VERSION 5.7 ;
  NOWIREEXTENSIONATPIN ON ;
  DIVIDERCHAR "/" ;
  BUSBITCHARS "[]" ;
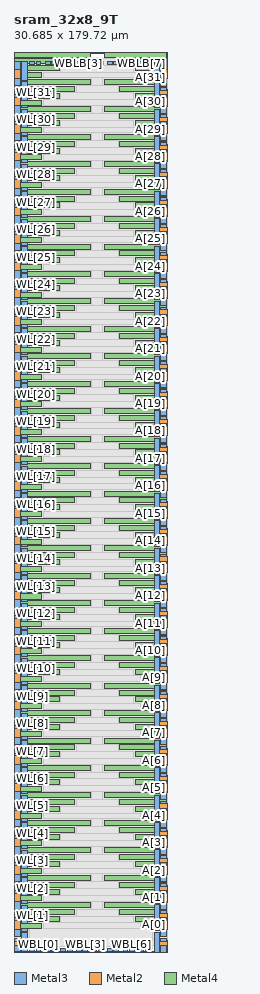
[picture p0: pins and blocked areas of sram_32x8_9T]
MACRO sram_32x8_9T
  CLASS BLOCK ;
  FOREIGN sram_32x8_9T ;
  ORIGIN 2.880 1.270 ;
  SIZE 30.685 BY 179.720 ;
  PIN VSS
    USE GROUND ;
    PORT
      LAYER Metal3 ;
        RECT -2.875 -1.250 -1.645 1.500 ;
    END
    PORT
      LAYER Metal3 ;
        RECT -2.875 1.785 -1.645 6.980 ;
    END
    PORT
      LAYER Metal3 ;
        RECT -2.875 7.265 -1.645 12.460 ;
    END
    PORT
      LAYER Metal3 ;
        RECT -2.875 12.745 -1.645 17.940 ;
    END
    PORT
      LAYER Metal3 ;
        RECT -2.875 18.225 -1.645 23.420 ;
    END
    PORT
      LAYER Metal3 ;
        RECT -2.875 23.705 -1.645 28.900 ;
    END
    PORT
      LAYER Metal3 ;
        RECT -2.875 29.185 -1.645 34.380 ;
    END
    PORT
      LAYER Metal3 ;
        RECT -2.875 34.665 -1.645 39.860 ;
    END
    PORT
      LAYER Metal3 ;
        RECT -2.875 40.145 -1.645 45.340 ;
    END
    PORT
      LAYER Metal3 ;
        RECT -2.875 45.625 -1.645 50.820 ;
    END
    PORT
      LAYER Metal3 ;
        RECT -2.875 51.105 -1.645 56.300 ;
    END
    PORT
      LAYER Metal3 ;
        RECT -2.875 56.585 -1.645 61.780 ;
    END
    PORT
      LAYER Metal3 ;
        RECT -2.875 62.065 -1.645 67.260 ;
    END
    PORT
      LAYER Metal3 ;
        RECT -2.875 67.545 -1.645 72.740 ;
    END
    PORT
      LAYER Metal3 ;
        RECT -2.875 73.025 -1.645 78.220 ;
    END
    PORT
      LAYER Metal3 ;
        RECT -2.875 78.505 -1.645 83.700 ;
    END
    PORT
      LAYER Metal3 ;
        RECT -2.875 83.985 -1.645 89.180 ;
    END
    PORT
      LAYER Metal3 ;
        RECT -2.875 89.465 -1.645 94.660 ;
    END
    PORT
      LAYER Metal3 ;
        RECT -2.875 94.945 -1.645 100.140 ;
    END
    PORT
      LAYER Metal3 ;
        RECT -2.875 100.425 -1.645 105.620 ;
    END
    PORT
      LAYER Metal3 ;
        RECT -2.875 105.905 -1.645 111.100 ;
    END
    PORT
      LAYER Metal3 ;
        RECT -2.875 111.385 -1.645 116.580 ;
    END
    PORT
      LAYER Metal3 ;
        RECT -2.875 116.865 -1.645 122.060 ;
    END
    PORT
      LAYER Metal3 ;
        RECT -2.875 122.345 -1.645 127.540 ;
    END
    PORT
      LAYER Metal3 ;
        RECT -2.875 127.825 -1.645 133.020 ;
    END
    PORT
      LAYER Metal3 ;
        RECT -2.875 133.305 -1.645 138.500 ;
    END
    PORT
      LAYER Metal3 ;
        RECT -2.875 138.785 -1.645 143.980 ;
    END
    PORT
      LAYER Metal3 ;
        RECT -2.875 144.265 -1.645 149.460 ;
    END
    PORT
      LAYER Metal3 ;
        RECT -2.875 149.745 -1.645 154.940 ;
    END
    PORT
      LAYER Metal3 ;
        RECT -2.875 155.225 -1.645 160.420 ;
    END
    PORT
      LAYER Metal3 ;
        RECT -2.875 160.705 -1.645 165.900 ;
    END
    PORT
      LAYER Metal3 ;
        RECT -2.875 166.185 -1.645 171.380 ;
    END
    PORT
      LAYER Metal3 ;
        RECT -2.875 171.665 -1.645 176.540 ;
    END
    PORT
      LAYER Metal3 ;
        RECT 26.440 171.640 27.580 176.545 ;
    END
    PORT
      LAYER Metal3 ;
        RECT 26.435 166.160 27.580 171.360 ;
    END
    PORT
      LAYER Metal3 ;
        RECT 26.435 160.680 27.580 165.880 ;
    END
    PORT
      LAYER Metal3 ;
        RECT 26.435 155.200 27.580 160.400 ;
    END
    PORT
      LAYER Metal3 ;
        RECT 26.435 149.720 27.580 154.920 ;
    END
    PORT
      LAYER Metal3 ;
        RECT 26.435 144.240 27.580 149.440 ;
    END
    PORT
      LAYER Metal3 ;
        RECT 26.435 138.760 27.580 143.960 ;
    END
    PORT
      LAYER Metal3 ;
        RECT 26.435 133.280 27.580 138.480 ;
    END
    PORT
      LAYER Metal3 ;
        RECT 26.435 127.800 27.580 133.000 ;
    END
    PORT
      LAYER Metal3 ;
        RECT 26.435 122.320 27.580 127.520 ;
    END
    PORT
      LAYER Metal3 ;
        RECT 26.435 116.840 27.580 122.040 ;
    END
    PORT
      LAYER Metal3 ;
        RECT 26.435 111.360 27.580 116.560 ;
    END
    PORT
      LAYER Metal3 ;
        RECT 26.435 105.880 27.580 111.080 ;
    END
    PORT
      LAYER Metal3 ;
        RECT 26.435 100.400 27.580 105.600 ;
    END
    PORT
      LAYER Metal3 ;
        RECT 26.435 94.920 27.580 100.120 ;
    END
    PORT
      LAYER Metal3 ;
        RECT 26.435 89.440 27.580 94.640 ;
    END
    PORT
      LAYER Metal3 ;
        RECT 26.435 83.960 27.580 89.160 ;
    END
    PORT
      LAYER Metal3 ;
        RECT 26.435 78.480 27.580 83.680 ;
    END
    PORT
      LAYER Metal3 ;
        RECT 26.435 73.000 27.580 78.200 ;
    END
    PORT
      LAYER Metal3 ;
        RECT 26.435 67.520 27.580 72.720 ;
    END
    PORT
      LAYER Metal3 ;
        RECT 26.435 62.040 27.580 67.240 ;
    END
    PORT
      LAYER Metal3 ;
        RECT 26.435 56.560 27.580 61.760 ;
    END
    PORT
      LAYER Metal3 ;
        RECT 26.435 51.080 27.580 56.280 ;
    END
    PORT
      LAYER Metal3 ;
        RECT 26.435 45.600 27.580 50.800 ;
    END
    PORT
      LAYER Metal3 ;
        RECT 26.435 40.120 27.580 45.320 ;
    END
    PORT
      LAYER Metal3 ;
        RECT 26.435 34.640 27.580 39.840 ;
    END
    PORT
      LAYER Metal3 ;
        RECT 26.435 29.160 27.580 34.360 ;
    END
    PORT
      LAYER Metal3 ;
        RECT 26.435 23.680 27.580 28.880 ;
    END
    PORT
      LAYER Metal3 ;
        RECT 26.435 18.200 27.580 23.400 ;
    END
    PORT
      LAYER Metal3 ;
        RECT 26.435 12.720 27.580 17.920 ;
    END
    PORT
      LAYER Metal3 ;
        RECT 26.435 7.240 27.580 12.440 ;
    END
    PORT
      LAYER Metal3 ;
        RECT 26.435 -1.270 27.580 1.480 ;
    END
    PORT
      LAYER Metal3 ;
        RECT 26.435 1.760 27.580 6.960 ;
    END
  END VSS
  PIN VDD
    USE POWER ;
    PORT
      LAYER Metal3 ;
        RECT -1.300 161.810 -0.130 167.010 ;
    END
    PORT
      LAYER Metal3 ;
        RECT -1.300 156.330 -0.130 161.530 ;
    END
    PORT
      LAYER Metal3 ;
        RECT -1.300 150.850 -0.130 156.050 ;
    END
    PORT
      LAYER Metal3 ;
        RECT -1.300 145.370 -0.130 150.570 ;
    END
    PORT
      LAYER Metal3 ;
        RECT -1.300 139.890 -0.130 145.090 ;
    END
    PORT
      LAYER Metal3 ;
        RECT -1.300 134.410 -0.130 139.610 ;
    END
    PORT
      LAYER Metal3 ;
        RECT -1.300 128.930 -0.130 134.130 ;
    END
    PORT
      LAYER Metal3 ;
        RECT -1.300 123.450 -0.130 128.650 ;
    END
    PORT
      LAYER Metal3 ;
        RECT -1.300 117.970 -0.130 123.170 ;
    END
    PORT
      LAYER Metal3 ;
        RECT -1.300 112.490 -0.130 117.690 ;
    END
    PORT
      LAYER Metal3 ;
        RECT -1.300 107.010 -0.130 112.210 ;
    END
    PORT
      LAYER Metal3 ;
        RECT -1.300 101.530 -0.130 106.730 ;
    END
    PORT
      LAYER Metal3 ;
        RECT -1.300 96.050 -0.130 101.250 ;
    END
    PORT
      LAYER Metal3 ;
        RECT -1.300 90.570 -0.130 95.770 ;
    END
    PORT
      LAYER Metal3 ;
        RECT -1.300 85.090 -0.130 90.290 ;
    END
    PORT
      LAYER Metal3 ;
        RECT -1.300 79.610 -0.130 84.810 ;
    END
    PORT
      LAYER Metal3 ;
        RECT -1.300 74.130 -0.130 79.330 ;
    END
    PORT
      LAYER Metal3 ;
        RECT -1.300 68.650 -0.130 73.850 ;
    END
    PORT
      LAYER Metal3 ;
        RECT -1.300 63.170 -0.130 68.370 ;
    END
    PORT
      LAYER Metal3 ;
        RECT -1.300 57.690 -0.130 62.890 ;
    END
    PORT
      LAYER Metal3 ;
        RECT -1.300 52.210 -0.130 57.410 ;
    END
    PORT
      LAYER Metal3 ;
        RECT -1.300 46.730 -0.130 51.930 ;
    END
    PORT
      LAYER Metal3 ;
        RECT -1.300 41.250 -0.130 46.450 ;
    END
    PORT
      LAYER Metal3 ;
        RECT -1.300 35.770 -0.130 40.970 ;
    END
    PORT
      LAYER Metal3 ;
        RECT -1.300 30.290 -0.130 35.490 ;
    END
    PORT
      LAYER Metal3 ;
        RECT -1.300 24.810 -0.130 30.010 ;
    END
    PORT
      LAYER Metal3 ;
        RECT -1.300 19.330 -0.130 24.530 ;
    END
    PORT
      LAYER Metal3 ;
        RECT -1.300 13.850 -0.130 19.050 ;
    END
    PORT
      LAYER Metal3 ;
        RECT -1.300 8.370 -0.130 13.570 ;
    END
    PORT
      LAYER Metal3 ;
        RECT -1.300 2.890 -0.130 8.090 ;
    END
    PORT
      LAYER Metal3 ;
        RECT -1.300 -1.240 -0.130 2.610 ;
    END
    PORT
      LAYER Metal3 ;
        RECT -1.300 167.290 -0.130 172.490 ;
    END
    PORT
      LAYER Metal3 ;
        RECT -1.300 172.770 -0.130 176.540 ;
    END
    PORT
      LAYER Metal3 ;
        RECT 25.135 -1.270 26.095 2.660 ;
    END
    PORT
      LAYER Metal3 ;
        RECT 25.135 2.940 26.095 8.140 ;
    END
    PORT
      LAYER Metal3 ;
        RECT 25.135 8.420 26.095 13.620 ;
    END
    PORT
      LAYER Metal3 ;
        RECT 25.135 13.900 26.095 19.100 ;
    END
    PORT
      LAYER Metal3 ;
        RECT 25.135 19.380 26.095 24.580 ;
    END
    PORT
      LAYER Metal3 ;
        RECT 25.135 24.860 26.095 30.060 ;
    END
    PORT
      LAYER Metal3 ;
        RECT 25.135 30.340 26.095 35.540 ;
    END
    PORT
      LAYER Metal3 ;
        RECT 25.135 35.820 26.095 41.020 ;
    END
    PORT
      LAYER Metal3 ;
        RECT 25.135 41.300 26.095 46.500 ;
    END
    PORT
      LAYER Metal3 ;
        RECT 25.135 46.780 26.095 51.980 ;
    END
    PORT
      LAYER Metal3 ;
        RECT 25.135 52.260 26.095 57.460 ;
    END
    PORT
      LAYER Metal3 ;
        RECT 25.135 57.740 26.095 62.940 ;
    END
    PORT
      LAYER Metal3 ;
        RECT 25.135 63.220 26.095 68.420 ;
    END
    PORT
      LAYER Metal3 ;
        RECT 25.135 68.700 26.095 73.900 ;
    END
    PORT
      LAYER Metal3 ;
        RECT 25.135 74.180 26.095 79.380 ;
    END
    PORT
      LAYER Metal3 ;
        RECT 25.135 79.660 26.095 84.860 ;
    END
    PORT
      LAYER Metal3 ;
        RECT 25.135 85.140 26.095 90.340 ;
    END
    PORT
      LAYER Metal3 ;
        RECT 25.135 90.620 26.095 95.820 ;
    END
    PORT
      LAYER Metal3 ;
        RECT 25.135 96.100 26.095 101.300 ;
    END
    PORT
      LAYER Metal3 ;
        RECT 25.135 101.580 26.095 106.780 ;
    END
    PORT
      LAYER Metal3 ;
        RECT 25.135 107.060 26.095 112.260 ;
    END
    PORT
      LAYER Metal3 ;
        RECT 25.135 112.540 26.095 117.740 ;
    END
    PORT
      LAYER Metal3 ;
        RECT 25.135 118.020 26.095 123.220 ;
    END
    PORT
      LAYER Metal3 ;
        RECT 25.135 123.500 26.095 128.700 ;
    END
    PORT
      LAYER Metal3 ;
        RECT 25.135 128.980 26.095 134.180 ;
    END
    PORT
      LAYER Metal3 ;
        RECT 25.135 134.460 26.095 139.660 ;
    END
    PORT
      LAYER Metal3 ;
        RECT 25.135 139.940 26.095 145.140 ;
    END
    PORT
      LAYER Metal3 ;
        RECT 25.135 145.420 26.095 150.620 ;
    END
    PORT
      LAYER Metal3 ;
        RECT 25.135 150.900 26.095 156.100 ;
    END
    PORT
      LAYER Metal3 ;
        RECT 25.135 156.380 26.095 161.580 ;
    END
    PORT
      LAYER Metal3 ;
        RECT 25.135 161.860 26.095 167.060 ;
    END
    PORT
      LAYER Metal3 ;
        RECT 25.135 167.340 26.095 172.540 ;
    END
    PORT
      LAYER Metal3 ;
        RECT 25.135 172.820 26.095 176.540 ;
    END
  END VDD
  PIN WBLB[0]
    ANTENNADIFFAREA 7.558400 ;
    PORT
      LAYER Metal3 ;
        RECT 0.260 -1.195 1.220 -0.500 ;
    END
    PORT
      LAYER Metal3 ;
        RECT 0.275 175.855 1.235 176.550 ;
    END
  END WBLB[0]
  PIN WBLB[1]
    ANTENNADIFFAREA 7.558400 ;
    PORT
      LAYER Metal3 ;
        RECT 3.370 -1.195 4.330 -0.500 ;
    END
    PORT
      LAYER Metal3 ;
        RECT 3.385 175.855 4.345 176.550 ;
    END
  END WBLB[1]
  PIN WBLB[2]
    ANTENNADIFFAREA 7.558400 ;
    PORT
      LAYER Metal3 ;
        RECT 6.480 -1.195 7.440 -0.500 ;
    END
    PORT
      LAYER Metal3 ;
        RECT 6.495 175.855 7.455 176.550 ;
    END
  END WBLB[2]
  PIN WBLB[3]
    ANTENNADIFFAREA 7.558400 ;
    PORT
      LAYER Metal3 ;
        RECT 9.590 -1.195 10.550 -0.500 ;
    END
    PORT
      LAYER Metal3 ;
        RECT 9.605 175.855 10.565 176.550 ;
    END
  END WBLB[3]
  PIN WBLB[4]
    ANTENNADIFFAREA 7.558400 ;
    PORT
      LAYER Metal3 ;
        RECT 12.700 -1.195 13.660 -0.500 ;
    END
    PORT
      LAYER Metal3 ;
        RECT 12.715 175.855 13.675 176.550 ;
    END
  END WBLB[4]
  PIN WBLB[5]
    ANTENNADIFFAREA 7.558400 ;
    PORT
      LAYER Metal3 ;
        RECT 15.810 -1.195 16.770 -0.500 ;
    END
    PORT
      LAYER Metal3 ;
        RECT 15.825 175.855 16.785 176.550 ;
    END
  END WBLB[5]
  PIN WBLB[6]
    ANTENNADIFFAREA 7.558400 ;
    PORT
      LAYER Metal3 ;
        RECT 18.920 -1.195 19.880 -0.500 ;
    END
    PORT
      LAYER Metal3 ;
        RECT 18.935 175.855 19.895 176.550 ;
    END
  END WBLB[6]
  PIN WBLB[7]
    ANTENNADIFFAREA 7.558400 ;
    PORT
      LAYER Metal3 ;
        RECT 22.030 -1.195 22.990 -0.500 ;
    END
    PORT
      LAYER Metal3 ;
        RECT 22.045 175.855 23.005 176.550 ;
    END
  END WBLB[7]
  PIN WBL[1]
    ANTENNADIFFAREA 5.459200 ;
    PORT
      LAYER Metal3 ;
        RECT 4.640 -1.190 5.600 -0.495 ;
    END
    PORT
      LAYER Metal3 ;
        RECT 4.640 175.860 5.600 176.550 ;
    END
  END WBL[1]
  PIN WBL[2]
    ANTENNADIFFAREA 5.459200 ;
    PORT
      LAYER Metal3 ;
        RECT 7.750 -1.190 8.710 -0.495 ;
    END
    PORT
      LAYER Metal3 ;
        RECT 7.750 175.860 8.710 176.550 ;
    END
  END WBL[2]
  PIN WBL[3]
    ANTENNADIFFAREA 5.459200 ;
    PORT
      LAYER Metal3 ;
        RECT 10.860 -1.190 11.820 -0.495 ;
    END
    PORT
      LAYER Metal3 ;
        RECT 10.860 175.860 11.820 176.550 ;
    END
  END WBL[3]
  PIN WBL[4]
    ANTENNADIFFAREA 5.459200 ;
    PORT
      LAYER Metal3 ;
        RECT 13.970 -1.190 14.930 -0.495 ;
    END
    PORT
      LAYER Metal3 ;
        RECT 13.970 175.860 14.930 176.550 ;
    END
  END WBL[4]
  PIN WBL[5]
    ANTENNADIFFAREA 5.459200 ;
    PORT
      LAYER Metal3 ;
        RECT 17.080 -1.190 18.040 -0.495 ;
    END
    PORT
      LAYER Metal3 ;
        RECT 17.080 175.860 18.040 176.550 ;
    END
  END WBL[5]
  PIN WBL[6]
    ANTENNADIFFAREA 5.459200 ;
    PORT
      LAYER Metal3 ;
        RECT 20.190 -1.190 21.150 -0.495 ;
    END
    PORT
      LAYER Metal3 ;
        RECT 20.190 175.860 21.150 176.550 ;
    END
  END WBL[6]
  PIN WBL[7]
    ANTENNADIFFAREA 5.459200 ;
    PORT
      LAYER Metal3 ;
        RECT 23.300 -1.190 24.260 -0.495 ;
    END
    PORT
      LAYER Metal3 ;
        RECT 23.300 175.860 24.260 176.550 ;
    END
  END WBL[7]
  PIN WBL[0]
    ANTENNADIFFAREA 5.459200 ;
    PORT
      LAYER Metal3 ;
        RECT 1.520 -1.190 2.480 -0.495 ;
    END
    PORT
      LAYER Metal3 ;
        RECT 1.530 175.860 2.490 176.550 ;
    END
  END WBL[0]
  PIN WL[0]
    ANTENNAGATEAREA 1.433600 ;
    PORT
      LAYER Metal2 ;
        RECT -2.850 0.080 -1.220 0.905 ;
    END
    PORT
      LAYER Metal2 ;
        RECT 26.175 0.080 27.805 0.905 ;
    END
  END WL[0]
  PIN WL[1]
    ANTENNAGATEAREA 1.433600 ;
    PORT
      LAYER Metal2 ;
        RECT -2.850 5.560 -1.220 6.385 ;
    END
    PORT
      LAYER Metal2 ;
        RECT 26.175 5.560 27.805 6.385 ;
    END
  END WL[1]
  PIN WL[2]
    ANTENNAGATEAREA 1.433600 ;
    PORT
      LAYER Metal2 ;
        RECT -2.850 11.040 -1.220 11.865 ;
    END
    PORT
      LAYER Metal2 ;
        RECT 26.175 11.040 27.805 11.865 ;
    END
  END WL[2]
  PIN WL[3]
    ANTENNAGATEAREA 1.433600 ;
    PORT
      LAYER Metal2 ;
        RECT -2.850 16.520 -1.220 17.345 ;
    END
    PORT
      LAYER Metal2 ;
        RECT 26.175 16.520 27.805 17.345 ;
    END
  END WL[3]
  PIN WL[4]
    ANTENNAGATEAREA 1.433600 ;
    PORT
      LAYER Metal2 ;
        RECT -2.850 22.000 -1.220 22.825 ;
    END
    PORT
      LAYER Metal2 ;
        RECT 26.175 22.000 27.805 22.825 ;
    END
  END WL[4]
  PIN WL[5]
    ANTENNAGATEAREA 1.433600 ;
    PORT
      LAYER Metal2 ;
        RECT -2.850 27.480 -1.220 28.305 ;
    END
    PORT
      LAYER Metal2 ;
        RECT 26.175 27.480 27.805 28.305 ;
    END
  END WL[5]
  PIN WL[6]
    ANTENNAGATEAREA 1.433600 ;
    PORT
      LAYER Metal2 ;
        RECT -2.850 32.960 -1.220 33.785 ;
    END
    PORT
      LAYER Metal2 ;
        RECT 26.175 32.960 27.805 33.785 ;
    END
  END WL[6]
  PIN WL[7]
    ANTENNAGATEAREA 1.433600 ;
    PORT
      LAYER Metal2 ;
        RECT -2.850 38.440 -1.220 39.265 ;
    END
    PORT
      LAYER Metal2 ;
        RECT 26.175 38.440 27.805 39.265 ;
    END
  END WL[7]
  PIN WL[8]
    ANTENNAGATEAREA 1.433600 ;
    PORT
      LAYER Metal2 ;
        RECT -2.850 43.920 -1.220 44.745 ;
    END
    PORT
      LAYER Metal2 ;
        RECT 26.175 43.920 27.805 44.745 ;
    END
  END WL[8]
  PIN WL[9]
    ANTENNAGATEAREA 1.433600 ;
    PORT
      LAYER Metal2 ;
        RECT -2.850 49.400 -1.220 50.225 ;
    END
    PORT
      LAYER Metal2 ;
        RECT 26.175 49.400 27.805 50.225 ;
    END
  END WL[9]
  PIN WL[10]
    ANTENNAGATEAREA 1.433600 ;
    PORT
      LAYER Metal2 ;
        RECT -2.850 54.880 -1.220 55.705 ;
    END
    PORT
      LAYER Metal2 ;
        RECT 26.175 54.880 27.805 55.705 ;
    END
  END WL[10]
  PIN WL[11]
    ANTENNAGATEAREA 1.433600 ;
    PORT
      LAYER Metal2 ;
        RECT -2.850 60.360 -1.220 61.185 ;
    END
    PORT
      LAYER Metal2 ;
        RECT 26.175 60.360 27.805 61.185 ;
    END
  END WL[11]
  PIN WL[12]
    ANTENNAGATEAREA 1.433600 ;
    PORT
      LAYER Metal2 ;
        RECT -2.850 65.840 -1.220 66.665 ;
    END
    PORT
      LAYER Metal2 ;
        RECT 26.175 65.840 27.805 66.665 ;
    END
  END WL[12]
  PIN WL[13]
    ANTENNAGATEAREA 1.433600 ;
    PORT
      LAYER Metal2 ;
        RECT -2.850 71.320 -1.220 72.145 ;
    END
    PORT
      LAYER Metal2 ;
        RECT 26.175 71.320 27.805 72.145 ;
    END
  END WL[13]
  PIN WL[14]
    ANTENNAGATEAREA 1.433600 ;
    PORT
      LAYER Metal2 ;
        RECT -2.850 76.800 -1.220 77.625 ;
    END
    PORT
      LAYER Metal2 ;
        RECT 26.175 76.800 27.805 77.625 ;
    END
  END WL[14]
  PIN WL[15]
    ANTENNAGATEAREA 1.433600 ;
    PORT
      LAYER Metal2 ;
        RECT -2.850 82.280 -1.220 83.105 ;
    END
    PORT
      LAYER Metal2 ;
        RECT 26.175 82.280 27.805 83.105 ;
    END
  END WL[15]
  PIN WL[16]
    ANTENNAGATEAREA 1.433600 ;
    PORT
      LAYER Metal2 ;
        RECT -2.850 87.760 -1.220 88.585 ;
    END
    PORT
      LAYER Metal2 ;
        RECT 26.175 87.760 27.805 88.585 ;
    END
  END WL[16]
  PIN WL[17]
    ANTENNAGATEAREA 1.433600 ;
    PORT
      LAYER Metal2 ;
        RECT -2.850 93.240 -1.220 94.065 ;
    END
    PORT
      LAYER Metal2 ;
        RECT 26.175 93.240 27.805 94.065 ;
    END
  END WL[17]
  PIN WL[18]
    ANTENNAGATEAREA 1.433600 ;
    PORT
      LAYER Metal2 ;
        RECT -2.850 98.720 -1.220 99.545 ;
    END
    PORT
      LAYER Metal2 ;
        RECT 26.175 98.720 27.805 99.545 ;
    END
  END WL[18]
  PIN WL[19]
    ANTENNAGATEAREA 1.433600 ;
    PORT
      LAYER Metal2 ;
        RECT -2.850 104.200 -1.220 105.025 ;
    END
    PORT
      LAYER Metal2 ;
        RECT 26.175 104.200 27.805 105.025 ;
    END
  END WL[19]
  PIN WL[20]
    ANTENNAGATEAREA 1.433600 ;
    PORT
      LAYER Metal2 ;
        RECT -2.850 109.680 -1.220 110.505 ;
    END
    PORT
      LAYER Metal2 ;
        RECT 26.175 109.680 27.805 110.505 ;
    END
  END WL[20]
  PIN WL[21]
    ANTENNAGATEAREA 1.433600 ;
    PORT
      LAYER Metal2 ;
        RECT -2.850 115.160 -1.220 115.985 ;
    END
    PORT
      LAYER Metal2 ;
        RECT 26.175 115.160 27.805 115.985 ;
    END
  END WL[21]
  PIN WL[22]
    ANTENNAGATEAREA 1.433600 ;
    PORT
      LAYER Metal2 ;
        RECT -2.850 120.640 -1.220 121.465 ;
    END
    PORT
      LAYER Metal2 ;
        RECT 26.175 120.640 27.805 121.465 ;
    END
  END WL[22]
  PIN WL[23]
    ANTENNAGATEAREA 1.433600 ;
    PORT
      LAYER Metal2 ;
        RECT -2.850 126.120 -1.220 126.945 ;
    END
    PORT
      LAYER Metal2 ;
        RECT 26.175 126.120 27.805 126.945 ;
    END
  END WL[23]
  PIN WL[24]
    ANTENNAGATEAREA 1.433600 ;
    PORT
      LAYER Metal2 ;
        RECT -2.850 131.600 -1.220 132.425 ;
    END
    PORT
      LAYER Metal2 ;
        RECT 26.175 131.600 27.805 132.425 ;
    END
  END WL[24]
  PIN WL[25]
    ANTENNAGATEAREA 1.433600 ;
    PORT
      LAYER Metal2 ;
        RECT -2.850 137.080 -1.220 137.905 ;
    END
    PORT
      LAYER Metal2 ;
        RECT 26.175 137.080 27.805 137.905 ;
    END
  END WL[25]
  PIN WL[26]
    ANTENNAGATEAREA 1.433600 ;
    PORT
      LAYER Metal2 ;
        RECT -2.850 142.560 -1.220 143.385 ;
    END
    PORT
      LAYER Metal2 ;
        RECT 26.175 142.560 27.805 143.385 ;
    END
  END WL[26]
  PIN WL[27]
    ANTENNAGATEAREA 1.433600 ;
    PORT
      LAYER Metal2 ;
        RECT -2.850 148.040 -1.220 148.865 ;
    END
    PORT
      LAYER Metal2 ;
        RECT 26.175 148.040 27.805 148.865 ;
    END
  END WL[27]
  PIN WL[28]
    ANTENNAGATEAREA 1.433600 ;
    PORT
      LAYER Metal2 ;
        RECT -2.850 153.520 -1.220 154.345 ;
    END
    PORT
      LAYER Metal2 ;
        RECT 26.175 153.520 27.805 154.345 ;
    END
  END WL[28]
  PIN WL[29]
    ANTENNAGATEAREA 1.433600 ;
    PORT
      LAYER Metal2 ;
        RECT -2.850 159.000 -1.220 159.825 ;
    END
    PORT
      LAYER Metal2 ;
        RECT 26.175 159.000 27.805 159.825 ;
    END
  END WL[29]
  PIN WL[30]
    ANTENNAGATEAREA 1.433600 ;
    PORT
      LAYER Metal2 ;
        RECT -2.850 164.480 -1.220 165.305 ;
    END
    PORT
      LAYER Metal2 ;
        RECT 26.175 164.480 27.805 165.305 ;
    END
  END WL[30]
  PIN WL[31]
    ANTENNAGATEAREA 1.433600 ;
    PORT
      LAYER Metal2 ;
        RECT -2.850 169.960 -1.220 170.785 ;
    END
    PORT
      LAYER Metal2 ;
        RECT 26.175 169.960 27.805 170.785 ;
    END
  END WL[31]
  PIN A[31]
    ANTENNADIFFAREA 2.832000 ;
    PORT
      LAYER Metal2 ;
        RECT -2.880 173.170 -1.625 174.875 ;
    END
    PORT
      LAYER Metal2 ;
        RECT 26.470 173.170 27.725 174.875 ;
    END
  END A[31]
  PIN A[30]
    ANTENNADIFFAREA 2.832000 ;
    PORT
      LAYER Metal2 ;
        RECT -2.880 167.690 -1.625 169.395 ;
    END
    PORT
      LAYER Metal2 ;
        RECT 26.470 167.690 27.725 169.395 ;
    END
  END A[30]
  PIN A[29]
    ANTENNADIFFAREA 2.832000 ;
    PORT
      LAYER Metal2 ;
        RECT -2.880 162.210 -1.625 163.915 ;
    END
    PORT
      LAYER Metal2 ;
        RECT 26.470 162.210 27.725 163.915 ;
    END
  END A[29]
  PIN A[28]
    ANTENNADIFFAREA 2.832000 ;
    PORT
      LAYER Metal2 ;
        RECT -2.880 156.730 -1.625 158.435 ;
    END
    PORT
      LAYER Metal2 ;
        RECT 26.470 156.730 27.725 158.435 ;
    END
  END A[28]
  PIN A[27]
    ANTENNADIFFAREA 2.832000 ;
    PORT
      LAYER Metal2 ;
        RECT -2.880 151.250 -1.625 152.955 ;
    END
    PORT
      LAYER Metal2 ;
        RECT 26.470 151.250 27.725 152.955 ;
    END
  END A[27]
  PIN A[26]
    ANTENNADIFFAREA 2.832000 ;
    PORT
      LAYER Metal2 ;
        RECT -2.880 145.770 -1.625 147.475 ;
    END
    PORT
      LAYER Metal2 ;
        RECT 26.470 145.770 27.725 147.475 ;
    END
  END A[26]
  PIN A[25]
    ANTENNADIFFAREA 2.832000 ;
    PORT
      LAYER Metal2 ;
        RECT -2.880 140.290 -1.625 141.995 ;
    END
    PORT
      LAYER Metal2 ;
        RECT 26.470 140.290 27.725 141.995 ;
    END
  END A[25]
  PIN A[24]
    ANTENNADIFFAREA 2.832000 ;
    PORT
      LAYER Metal2 ;
        RECT -2.880 134.810 -1.625 136.515 ;
    END
    PORT
      LAYER Metal2 ;
        RECT 26.470 134.810 27.725 136.515 ;
    END
  END A[24]
  PIN A[23]
    ANTENNADIFFAREA 2.832000 ;
    PORT
      LAYER Metal2 ;
        RECT -2.880 129.330 -1.625 131.035 ;
    END
    PORT
      LAYER Metal2 ;
        RECT 26.470 129.330 27.725 131.035 ;
    END
  END A[23]
  PIN A[22]
    ANTENNADIFFAREA 2.832000 ;
    PORT
      LAYER Metal2 ;
        RECT -2.880 123.850 -1.625 125.555 ;
    END
    PORT
      LAYER Metal2 ;
        RECT 26.470 123.850 27.725 125.555 ;
    END
  END A[22]
  PIN A[21]
    ANTENNADIFFAREA 2.832000 ;
    PORT
      LAYER Metal2 ;
        RECT -2.880 118.370 -1.625 120.075 ;
    END
    PORT
      LAYER Metal2 ;
        RECT 26.470 118.370 27.725 120.075 ;
    END
  END A[21]
  PIN A[20]
    ANTENNADIFFAREA 2.832000 ;
    PORT
      LAYER Metal2 ;
        RECT -2.880 112.890 -1.625 114.595 ;
    END
    PORT
      LAYER Metal2 ;
        RECT 26.470 112.890 27.725 114.595 ;
    END
  END A[20]
  PIN A[19]
    ANTENNADIFFAREA 2.832000 ;
    PORT
      LAYER Metal2 ;
        RECT -2.880 107.410 -1.625 109.115 ;
    END
    PORT
      LAYER Metal2 ;
        RECT 26.470 107.410 27.725 109.115 ;
    END
  END A[19]
  PIN A[18]
    ANTENNADIFFAREA 2.832000 ;
    PORT
      LAYER Metal2 ;
        RECT -2.880 101.930 -1.625 103.635 ;
    END
    PORT
      LAYER Metal2 ;
        RECT 26.470 101.930 27.725 103.635 ;
    END
  END A[18]
  PIN A[17]
    ANTENNADIFFAREA 2.832000 ;
    PORT
      LAYER Metal2 ;
        RECT -2.880 96.450 -1.625 98.155 ;
    END
    PORT
      LAYER Metal2 ;
        RECT 26.470 96.450 27.725 98.155 ;
    END
  END A[17]
  PIN A[16]
    ANTENNADIFFAREA 2.832000 ;
    PORT
      LAYER Metal2 ;
        RECT -2.880 90.970 -1.625 92.675 ;
    END
    PORT
      LAYER Metal2 ;
        RECT 26.470 90.970 27.725 92.675 ;
    END
  END A[16]
  PIN A[15]
    ANTENNADIFFAREA 2.832000 ;
    PORT
      LAYER Metal2 ;
        RECT -2.880 85.490 -1.625 87.195 ;
    END
    PORT
      LAYER Metal2 ;
        RECT 26.470 85.490 27.725 87.195 ;
    END
  END A[15]
  PIN A[14]
    ANTENNADIFFAREA 2.832000 ;
    PORT
      LAYER Metal2 ;
        RECT -2.880 80.010 -1.625 81.715 ;
    END
    PORT
      LAYER Metal2 ;
        RECT 26.470 80.010 27.725 81.715 ;
    END
  END A[14]
  PIN A[13]
    ANTENNADIFFAREA 2.832000 ;
    PORT
      LAYER Metal2 ;
        RECT -2.880 74.530 -1.625 76.235 ;
    END
    PORT
      LAYER Metal2 ;
        RECT 26.470 74.530 27.725 76.235 ;
    END
  END A[13]
  PIN A[12]
    ANTENNADIFFAREA 2.832000 ;
    PORT
      LAYER Metal2 ;
        RECT -2.880 69.050 -1.625 70.755 ;
    END
    PORT
      LAYER Metal2 ;
        RECT 26.470 69.050 27.725 70.755 ;
    END
  END A[12]
  PIN A[11]
    ANTENNADIFFAREA 2.832000 ;
    PORT
      LAYER Metal2 ;
        RECT -2.880 63.570 -1.625 65.275 ;
    END
    PORT
      LAYER Metal2 ;
        RECT 26.470 63.570 27.725 65.275 ;
    END
  END A[11]
  PIN A[10]
    ANTENNADIFFAREA 2.832000 ;
    PORT
      LAYER Metal2 ;
        RECT -2.880 58.090 -1.625 59.795 ;
    END
    PORT
      LAYER Metal2 ;
        RECT 26.470 58.090 27.725 59.795 ;
    END
  END A[10]
  PIN A[9]
    ANTENNADIFFAREA 2.832000 ;
    PORT
      LAYER Metal2 ;
        RECT -2.880 52.610 -1.625 54.315 ;
    END
    PORT
      LAYER Metal2 ;
        RECT 26.470 52.610 27.725 54.315 ;
    END
  END A[9]
  PIN A[8]
    ANTENNADIFFAREA 2.832000 ;
    PORT
      LAYER Metal2 ;
        RECT -2.880 47.130 -1.625 48.835 ;
    END
    PORT
      LAYER Metal2 ;
        RECT 26.470 47.130 27.725 48.835 ;
    END
  END A[8]
  PIN A[7]
    ANTENNADIFFAREA 2.832000 ;
    PORT
      LAYER Metal2 ;
        RECT -2.880 41.650 -1.625 43.355 ;
    END
    PORT
      LAYER Metal2 ;
        RECT 26.470 41.650 27.725 43.355 ;
    END
  END A[7]
  PIN A[6]
    ANTENNADIFFAREA 2.832000 ;
    PORT
      LAYER Metal2 ;
        RECT -2.880 36.170 -1.625 37.875 ;
    END
    PORT
      LAYER Metal2 ;
        RECT 26.470 36.170 27.725 37.875 ;
    END
  END A[6]
  PIN A[5]
    ANTENNADIFFAREA 2.832000 ;
    PORT
      LAYER Metal2 ;
        RECT -2.880 30.690 -1.625 32.395 ;
    END
    PORT
      LAYER Metal2 ;
        RECT 26.470 30.690 27.725 32.395 ;
    END
  END A[5]
  PIN A[4]
    ANTENNADIFFAREA 2.832000 ;
    PORT
      LAYER Metal2 ;
        RECT -2.880 25.210 -1.625 26.915 ;
    END
    PORT
      LAYER Metal2 ;
        RECT 26.470 25.210 27.725 26.915 ;
    END
  END A[4]
  PIN A[3]
    ANTENNADIFFAREA 2.832000 ;
    PORT
      LAYER Metal2 ;
        RECT -2.880 19.730 -1.625 21.435 ;
    END
    PORT
      LAYER Metal2 ;
        RECT 26.470 19.730 27.725 21.435 ;
    END
  END A[3]
  PIN A[2]
    ANTENNADIFFAREA 2.832000 ;
    PORT
      LAYER Metal2 ;
        RECT -2.880 14.250 -1.625 15.955 ;
    END
    PORT
      LAYER Metal2 ;
        RECT 26.470 14.250 27.725 15.955 ;
    END
  END A[2]
  PIN A[1]
    ANTENNADIFFAREA 2.832000 ;
    PORT
      LAYER Metal2 ;
        RECT -2.880 8.770 -1.625 10.475 ;
    END
    PORT
      LAYER Metal2 ;
        RECT 26.470 8.770 27.725 10.475 ;
    END
  END A[1]
  PIN A[0]
    ANTENNADIFFAREA 2.832000 ;
    PORT
      LAYER Metal2 ;
        RECT -2.880 3.290 -1.625 4.995 ;
    END
    PORT
      LAYER Metal2 ;
        RECT 26.470 3.290 27.725 4.995 ;
    END
  END A[0]
  PIN RBL[0]
    ANTENNADIFFAREA 0.511400 ;
    PORT
      LAYER Metal4 ;
        RECT -2.800 3.460 2.710 4.460 ;
    END
  END RBL[0]
  PIN RBL[8]
    ANTENNADIFFAREA 0.511400 ;
    PORT
      LAYER Metal4 ;
        RECT -2.800 8.940 2.710 9.940 ;
    END
  END RBL[8]
  PIN RBL[16]
    ANTENNADIFFAREA 0.511400 ;
    PORT
      LAYER Metal4 ;
        RECT -2.800 14.420 2.710 15.420 ;
    END
  END RBL[16]
  PIN RBL[24]
    ANTENNADIFFAREA 0.511400 ;
    PORT
      LAYER Metal4 ;
        RECT -2.800 19.900 2.710 20.900 ;
    END
  END RBL[24]
  PIN RBL[32]
    ANTENNADIFFAREA 0.511400 ;
    PORT
      LAYER Metal4 ;
        RECT -2.800 25.380 2.710 26.380 ;
    END
  END RBL[32]
  PIN RBL[40]
    ANTENNADIFFAREA 0.511400 ;
    PORT
      LAYER Metal4 ;
        RECT -2.800 30.860 2.710 31.860 ;
    END
  END RBL[40]
  PIN RBL[48]
    ANTENNADIFFAREA 0.511400 ;
    PORT
      LAYER Metal4 ;
        RECT -2.800 36.340 2.710 37.340 ;
    END
  END RBL[48]
  PIN RBL[56]
    ANTENNADIFFAREA 0.511400 ;
    PORT
      LAYER Metal4 ;
        RECT -2.800 41.820 2.710 42.820 ;
    END
  END RBL[56]
  PIN RBL[64]
    ANTENNADIFFAREA 0.511400 ;
    PORT
      LAYER Metal4 ;
        RECT -2.800 47.300 2.710 48.300 ;
    END
  END RBL[64]
  PIN RBL[72]
    ANTENNADIFFAREA 0.511400 ;
    PORT
      LAYER Metal4 ;
        RECT -2.800 52.780 2.710 53.780 ;
    END
  END RBL[72]
  PIN RBL[80]
    ANTENNADIFFAREA 0.511400 ;
    PORT
      LAYER Metal4 ;
        RECT -2.800 58.260 2.710 59.260 ;
    END
  END RBL[80]
  PIN RBL[88]
    ANTENNADIFFAREA 0.511400 ;
    PORT
      LAYER Metal4 ;
        RECT -2.800 63.740 2.710 64.740 ;
    END
  END RBL[88]
  PIN RBL[96]
    ANTENNADIFFAREA 0.511400 ;
    PORT
      LAYER Metal4 ;
        RECT -2.800 69.220 2.710 70.220 ;
    END
  END RBL[96]
  PIN RBL[104]
    ANTENNADIFFAREA 0.511400 ;
    PORT
      LAYER Metal4 ;
        RECT -2.800 74.700 2.710 75.700 ;
    END
  END RBL[104]
  PIN RBL[112]
    ANTENNADIFFAREA 0.511400 ;
    PORT
      LAYER Metal4 ;
        RECT -2.800 80.180 2.710 81.180 ;
    END
  END RBL[112]
  PIN RBL[120]
    ANTENNADIFFAREA 0.511400 ;
    PORT
      LAYER Metal4 ;
        RECT -2.800 85.660 2.710 86.660 ;
    END
  END RBL[120]
  PIN RBL[128]
    ANTENNADIFFAREA 0.511400 ;
    PORT
      LAYER Metal4 ;
        RECT -2.800 91.140 2.710 92.140 ;
    END
  END RBL[128]
  PIN RBL[136]
    ANTENNADIFFAREA 0.511400 ;
    PORT
      LAYER Metal4 ;
        RECT -2.800 96.620 2.710 97.620 ;
    END
  END RBL[136]
  PIN RBL[144]
    ANTENNADIFFAREA 0.511400 ;
    PORT
      LAYER Metal4 ;
        RECT -2.800 102.100 2.710 103.100 ;
    END
  END RBL[144]
  PIN RBL[152]
    ANTENNADIFFAREA 0.511400 ;
    PORT
      LAYER Metal4 ;
        RECT -2.800 107.580 2.710 108.580 ;
    END
  END RBL[152]
  PIN RBL[160]
    ANTENNADIFFAREA 0.511400 ;
    PORT
      LAYER Metal4 ;
        RECT -2.800 113.060 2.710 114.060 ;
    END
  END RBL[160]
  PIN RBL[168]
    ANTENNADIFFAREA 0.511400 ;
    PORT
      LAYER Metal4 ;
        RECT -2.800 118.540 2.710 119.540 ;
    END
  END RBL[168]
  PIN RBL[176]
    ANTENNADIFFAREA 0.511400 ;
    PORT
      LAYER Metal4 ;
        RECT -2.800 124.020 2.710 125.020 ;
    END
  END RBL[176]
  PIN RBL[184]
    ANTENNADIFFAREA 0.511400 ;
    PORT
      LAYER Metal4 ;
        RECT -2.800 129.500 2.710 130.500 ;
    END
  END RBL[184]
  PIN RBL[192]
    ANTENNADIFFAREA 0.511400 ;
    PORT
      LAYER Metal4 ;
        RECT -2.800 134.980 2.710 135.980 ;
    END
  END RBL[192]
  PIN RBL[200]
    ANTENNADIFFAREA 0.511400 ;
    PORT
      LAYER Metal4 ;
        RECT -2.800 140.460 2.710 141.460 ;
    END
  END RBL[200]
  PIN RBL[208]
    ANTENNADIFFAREA 0.511400 ;
    PORT
      LAYER Metal4 ;
        RECT -2.800 145.940 2.710 146.940 ;
    END
  END RBL[208]
  PIN RBL[216]
    ANTENNADIFFAREA 0.511400 ;
    PORT
      LAYER Metal4 ;
        RECT -2.800 151.420 2.710 152.420 ;
    END
  END RBL[216]
  PIN RBL[224]
    ANTENNADIFFAREA 0.511400 ;
    PORT
      LAYER Metal4 ;
        RECT -2.800 156.900 2.710 157.900 ;
    END
  END RBL[224]
  PIN RBL[232]
    ANTENNADIFFAREA 0.511400 ;
    PORT
      LAYER Metal4 ;
        RECT -2.800 162.380 2.710 163.380 ;
    END
  END RBL[232]
  PIN RBL[240]
    ANTENNADIFFAREA 0.511400 ;
    PORT
      LAYER Metal4 ;
        RECT -2.800 167.860 2.710 168.860 ;
    END
  END RBL[240]
  PIN RBL[248]
    ANTENNADIFFAREA 0.511400 ;
    PORT
      LAYER Metal4 ;
        RECT -2.800 173.340 2.710 174.340 ;
    END
  END RBL[248]
  PIN RBL[7]
    ANTENNADIFFAREA 0.511400 ;
    PORT
      LAYER Metal4 ;
        RECT 24.490 3.460 27.535 4.460 ;
    END
  END RBL[7]
  PIN RBL[15]
    ANTENNADIFFAREA 0.511400 ;
    PORT
      LAYER Metal4 ;
        RECT 24.490 8.940 27.535 9.940 ;
    END
  END RBL[15]
  PIN RBL[23]
    ANTENNADIFFAREA 0.511400 ;
    PORT
      LAYER Metal4 ;
        RECT 24.490 14.420 27.535 15.420 ;
    END
  END RBL[23]
  PIN RBL[31]
    ANTENNADIFFAREA 0.511400 ;
    PORT
      LAYER Metal4 ;
        RECT 24.490 19.900 27.535 20.900 ;
    END
  END RBL[31]
  PIN RBL[39]
    ANTENNADIFFAREA 0.511400 ;
    PORT
      LAYER Metal4 ;
        RECT 24.490 25.380 27.535 26.380 ;
    END
  END RBL[39]
  PIN RBL[47]
    ANTENNADIFFAREA 0.511400 ;
    PORT
      LAYER Metal4 ;
        RECT 24.490 30.860 27.535 31.860 ;
    END
  END RBL[47]
  PIN RBL[55]
    ANTENNADIFFAREA 0.511400 ;
    PORT
      LAYER Metal4 ;
        RECT 24.490 36.340 27.535 37.340 ;
    END
  END RBL[55]
  PIN RBL[63]
    ANTENNADIFFAREA 0.511400 ;
    PORT
      LAYER Metal4 ;
        RECT 24.490 41.820 27.535 42.820 ;
    END
  END RBL[63]
  PIN RBL[71]
    ANTENNADIFFAREA 0.511400 ;
    PORT
      LAYER Metal4 ;
        RECT 24.490 47.300 27.535 48.300 ;
    END
  END RBL[71]
  PIN RBL[79]
    ANTENNADIFFAREA 0.511400 ;
    PORT
      LAYER Metal4 ;
        RECT 24.490 52.780 27.535 53.780 ;
    END
  END RBL[79]
  PIN RBL[87]
    ANTENNADIFFAREA 0.511400 ;
    PORT
      LAYER Metal4 ;
        RECT 24.490 58.260 27.535 59.260 ;
    END
  END RBL[87]
  PIN RBL[95]
    ANTENNADIFFAREA 0.511400 ;
    PORT
      LAYER Metal4 ;
        RECT 24.490 63.740 27.535 64.740 ;
    END
  END RBL[95]
  PIN RBL[103]
    ANTENNADIFFAREA 0.511400 ;
    PORT
      LAYER Metal4 ;
        RECT 24.490 69.220 27.535 70.220 ;
    END
  END RBL[103]
  PIN RBL[111]
    ANTENNADIFFAREA 0.511400 ;
    PORT
      LAYER Metal4 ;
        RECT 24.490 74.700 27.535 75.700 ;
    END
  END RBL[111]
  PIN RBL[119]
    ANTENNADIFFAREA 0.511400 ;
    PORT
      LAYER Metal4 ;
        RECT 24.490 80.180 27.535 81.180 ;
    END
  END RBL[119]
  PIN RBL[127]
    ANTENNADIFFAREA 0.511400 ;
    PORT
      LAYER Metal4 ;
        RECT 24.490 85.660 27.535 86.660 ;
    END
  END RBL[127]
  PIN RBL[135]
    ANTENNADIFFAREA 0.511400 ;
    PORT
      LAYER Metal4 ;
        RECT 24.490 91.140 27.535 92.140 ;
    END
  END RBL[135]
  PIN RBL[143]
    ANTENNADIFFAREA 0.511400 ;
    PORT
      LAYER Metal4 ;
        RECT 24.490 96.620 27.535 97.620 ;
    END
  END RBL[143]
  PIN RBL[151]
    ANTENNADIFFAREA 0.511400 ;
    PORT
      LAYER Metal4 ;
        RECT 24.490 102.100 27.535 103.100 ;
    END
  END RBL[151]
  PIN RBL[159]
    ANTENNADIFFAREA 0.511400 ;
    PORT
      LAYER Metal4 ;
        RECT 24.490 107.580 27.535 108.580 ;
    END
  END RBL[159]
  PIN RBL[167]
    ANTENNADIFFAREA 0.511400 ;
    PORT
      LAYER Metal4 ;
        RECT 24.490 113.060 27.535 114.060 ;
    END
  END RBL[167]
  PIN RBL[175]
    ANTENNADIFFAREA 0.511400 ;
    PORT
      LAYER Metal4 ;
        RECT 24.490 118.540 27.535 119.540 ;
    END
  END RBL[175]
  PIN RBL[183]
    ANTENNADIFFAREA 0.511400 ;
    PORT
      LAYER Metal4 ;
        RECT 24.490 124.020 27.535 125.020 ;
    END
  END RBL[183]
  PIN RBL[191]
    ANTENNADIFFAREA 0.511400 ;
    PORT
      LAYER Metal4 ;
        RECT 24.490 129.500 27.535 130.500 ;
    END
  END RBL[191]
  PIN RBL[199]
    ANTENNADIFFAREA 0.511400 ;
    PORT
      LAYER Metal4 ;
        RECT 24.490 134.980 27.535 135.980 ;
    END
  END RBL[199]
  PIN RBL[207]
    ANTENNADIFFAREA 0.511400 ;
    PORT
      LAYER Metal4 ;
        RECT 24.490 140.460 27.535 141.460 ;
    END
  END RBL[207]
  PIN RBL[215]
    ANTENNADIFFAREA 0.511400 ;
    PORT
      LAYER Metal4 ;
        RECT 24.490 145.940 27.535 146.940 ;
    END
  END RBL[215]
  PIN RBL[223]
    ANTENNADIFFAREA 0.511400 ;
    PORT
      LAYER Metal4 ;
        RECT 24.490 151.420 27.535 152.420 ;
    END
  END RBL[223]
  PIN RBL[231]
    ANTENNADIFFAREA 0.511400 ;
    PORT
      LAYER Metal4 ;
        RECT 24.490 156.900 27.535 157.900 ;
    END
  END RBL[231]
  PIN RBL[239]
    ANTENNADIFFAREA 0.511400 ;
    PORT
      LAYER Metal4 ;
        RECT 24.490 162.380 27.535 163.380 ;
    END
  END RBL[239]
  PIN RBL[247]
    ANTENNADIFFAREA 0.511400 ;
    PORT
      LAYER Metal4 ;
        RECT 24.490 167.860 27.535 168.860 ;
    END
  END RBL[247]
  PIN RBL[255]
    ANTENNADIFFAREA 0.511400 ;
    PORT
      LAYER Metal4 ;
        RECT 24.490 173.340 27.535 174.340 ;
    END
  END RBL[255]
  PIN RBL[6]
    ANTENNADIFFAREA 0.511400 ;
    PORT
      LAYER Metal4 ;
        RECT 21.380 4.830 27.535 5.830 ;
    END
  END RBL[6]
  PIN RBL[14]
    ANTENNADIFFAREA 0.511400 ;
    PORT
      LAYER Metal4 ;
        RECT 21.380 10.310 27.535 11.310 ;
    END
  END RBL[14]
  PIN RBL[22]
    ANTENNADIFFAREA 0.511400 ;
    PORT
      LAYER Metal4 ;
        RECT 21.380 15.790 27.535 16.790 ;
    END
  END RBL[22]
  PIN RBL[30]
    ANTENNADIFFAREA 0.511400 ;
    PORT
      LAYER Metal4 ;
        RECT 21.380 21.270 27.535 22.270 ;
    END
  END RBL[30]
  PIN RBL[38]
    ANTENNADIFFAREA 0.511400 ;
    PORT
      LAYER Metal4 ;
        RECT 21.380 26.750 27.535 27.750 ;
    END
  END RBL[38]
  PIN RBL[46]
    ANTENNADIFFAREA 0.511400 ;
    PORT
      LAYER Metal4 ;
        RECT 21.380 32.230 27.535 33.230 ;
    END
  END RBL[46]
  PIN RBL[54]
    ANTENNADIFFAREA 0.511400 ;
    PORT
      LAYER Metal4 ;
        RECT 21.380 37.710 27.535 38.710 ;
    END
  END RBL[54]
  PIN RBL[62]
    ANTENNADIFFAREA 0.511400 ;
    PORT
      LAYER Metal4 ;
        RECT 21.380 43.190 27.535 44.190 ;
    END
  END RBL[62]
  PIN RBL[70]
    ANTENNADIFFAREA 0.511400 ;
    PORT
      LAYER Metal4 ;
        RECT 21.380 48.670 27.535 49.670 ;
    END
  END RBL[70]
  PIN RBL[78]
    ANTENNADIFFAREA 0.511400 ;
    PORT
      LAYER Metal4 ;
        RECT 21.380 54.150 27.535 55.150 ;
    END
  END RBL[78]
  PIN RBL[86]
    ANTENNADIFFAREA 0.511400 ;
    PORT
      LAYER Metal4 ;
        RECT 21.380 59.630 27.535 60.630 ;
    END
  END RBL[86]
  PIN RBL[94]
    ANTENNADIFFAREA 0.511400 ;
    PORT
      LAYER Metal4 ;
        RECT 21.380 65.110 27.535 66.110 ;
    END
  END RBL[94]
  PIN RBL[102]
    ANTENNADIFFAREA 0.511400 ;
    PORT
      LAYER Metal4 ;
        RECT 21.380 70.590 27.535 71.590 ;
    END
  END RBL[102]
  PIN RBL[110]
    ANTENNADIFFAREA 0.511400 ;
    PORT
      LAYER Metal4 ;
        RECT 21.380 76.070 27.535 77.070 ;
    END
  END RBL[110]
  PIN RBL[118]
    ANTENNADIFFAREA 0.511400 ;
    PORT
      LAYER Metal4 ;
        RECT 21.380 81.550 27.535 82.550 ;
    END
  END RBL[118]
  PIN RBL[126]
    ANTENNADIFFAREA 0.511400 ;
    PORT
      LAYER Metal4 ;
        RECT 21.380 87.030 27.535 88.030 ;
    END
  END RBL[126]
  PIN RBL[134]
    ANTENNADIFFAREA 0.511400 ;
    PORT
      LAYER Metal4 ;
        RECT 21.380 92.510 27.535 93.510 ;
    END
  END RBL[134]
  PIN RBL[142]
    ANTENNADIFFAREA 0.511400 ;
    PORT
      LAYER Metal4 ;
        RECT 21.380 97.990 27.535 98.990 ;
    END
  END RBL[142]
  PIN RBL[150]
    ANTENNADIFFAREA 0.511400 ;
    PORT
      LAYER Metal4 ;
        RECT 21.380 103.470 27.535 104.470 ;
    END
  END RBL[150]
  PIN RBL[158]
    ANTENNADIFFAREA 0.511400 ;
    PORT
      LAYER Metal4 ;
        RECT 21.380 108.950 27.535 109.950 ;
    END
  END RBL[158]
  PIN RBL[166]
    ANTENNADIFFAREA 0.511400 ;
    PORT
      LAYER Metal4 ;
        RECT 21.380 114.430 27.535 115.430 ;
    END
  END RBL[166]
  PIN RBL[174]
    ANTENNADIFFAREA 0.511400 ;
    PORT
      LAYER Metal4 ;
        RECT 21.380 119.910 27.535 120.910 ;
    END
  END RBL[174]
  PIN RBL[182]
    ANTENNADIFFAREA 0.511400 ;
    PORT
      LAYER Metal4 ;
        RECT 21.380 125.390 27.535 126.390 ;
    END
  END RBL[182]
  PIN RBL[190]
    ANTENNADIFFAREA 0.511400 ;
    PORT
      LAYER Metal4 ;
        RECT 21.380 130.870 27.535 131.870 ;
    END
  END RBL[190]
  PIN RBL[198]
    ANTENNADIFFAREA 0.511400 ;
    PORT
      LAYER Metal4 ;
        RECT 21.380 136.350 27.535 137.350 ;
    END
  END RBL[198]
  PIN RBL[206]
    ANTENNADIFFAREA 0.511400 ;
    PORT
      LAYER Metal4 ;
        RECT 21.380 141.830 27.535 142.830 ;
    END
  END RBL[206]
  PIN RBL[214]
    ANTENNADIFFAREA 0.511400 ;
    PORT
      LAYER Metal4 ;
        RECT 21.380 147.310 27.535 148.310 ;
    END
  END RBL[214]
  PIN RBL[222]
    ANTENNADIFFAREA 0.511400 ;
    PORT
      LAYER Metal4 ;
        RECT 21.380 152.790 27.535 153.790 ;
    END
  END RBL[222]
  PIN RBL[230]
    ANTENNADIFFAREA 0.511400 ;
    PORT
      LAYER Metal4 ;
        RECT 21.380 158.270 27.535 159.270 ;
    END
  END RBL[230]
  PIN RBL[238]
    ANTENNADIFFAREA 0.511400 ;
    PORT
      LAYER Metal4 ;
        RECT 21.380 163.750 27.535 164.750 ;
    END
  END RBL[238]
  PIN RBL[246]
    ANTENNADIFFAREA 0.511400 ;
    PORT
      LAYER Metal4 ;
        RECT 21.380 169.230 27.535 170.230 ;
    END
  END RBL[246]
  PIN RBL[254]
    ANTENNADIFFAREA 0.511400 ;
    PORT
      LAYER Metal4 ;
        RECT 21.380 174.710 27.535 175.710 ;
    END
  END RBL[254]
  PIN RBL[5]
    ANTENNADIFFAREA 0.511400 ;
    PORT
      LAYER Metal4 ;
        RECT 18.270 6.200 27.535 7.200 ;
    END
  END RBL[5]
  PIN RBL[13]
    ANTENNADIFFAREA 0.511400 ;
    PORT
      LAYER Metal4 ;
        RECT 18.270 11.680 27.535 12.680 ;
    END
  END RBL[13]
  PIN RBL[21]
    ANTENNADIFFAREA 0.511400 ;
    PORT
      LAYER Metal4 ;
        RECT 18.270 17.160 27.535 18.160 ;
    END
  END RBL[21]
  PIN RBL[29]
    ANTENNADIFFAREA 0.511400 ;
    PORT
      LAYER Metal4 ;
        RECT 18.270 22.640 27.535 23.640 ;
    END
  END RBL[29]
  PIN RBL[37]
    ANTENNADIFFAREA 0.511400 ;
    PORT
      LAYER Metal4 ;
        RECT 18.270 28.120 27.535 29.120 ;
    END
  END RBL[37]
  PIN RBL[45]
    ANTENNADIFFAREA 0.511400 ;
    PORT
      LAYER Metal4 ;
        RECT 18.270 33.600 27.535 34.600 ;
    END
  END RBL[45]
  PIN RBL[53]
    ANTENNADIFFAREA 0.511400 ;
    PORT
      LAYER Metal4 ;
        RECT 18.270 39.080 27.535 40.080 ;
    END
  END RBL[53]
  PIN RBL[61]
    ANTENNADIFFAREA 0.511400 ;
    PORT
      LAYER Metal4 ;
        RECT 18.270 44.560 27.535 45.560 ;
    END
  END RBL[61]
  PIN RBL[69]
    ANTENNADIFFAREA 0.511400 ;
    PORT
      LAYER Metal4 ;
        RECT 18.270 50.040 27.535 51.040 ;
    END
  END RBL[69]
  PIN RBL[77]
    ANTENNADIFFAREA 0.511400 ;
    PORT
      LAYER Metal4 ;
        RECT 18.270 55.520 27.535 56.520 ;
    END
  END RBL[77]
  PIN RBL[85]
    ANTENNADIFFAREA 0.511400 ;
    PORT
      LAYER Metal4 ;
        RECT 18.270 61.000 27.535 62.000 ;
    END
  END RBL[85]
  PIN RBL[93]
    ANTENNADIFFAREA 0.511400 ;
    PORT
      LAYER Metal4 ;
        RECT 18.270 66.480 27.535 67.480 ;
    END
  END RBL[93]
  PIN RBL[101]
    ANTENNADIFFAREA 0.511400 ;
    PORT
      LAYER Metal4 ;
        RECT 18.270 71.960 27.535 72.960 ;
    END
  END RBL[101]
  PIN RBL[109]
    ANTENNADIFFAREA 0.511400 ;
    PORT
      LAYER Metal4 ;
        RECT 18.270 77.440 27.535 78.440 ;
    END
  END RBL[109]
  PIN RBL[117]
    ANTENNADIFFAREA 0.511400 ;
    PORT
      LAYER Metal4 ;
        RECT 18.270 82.920 27.535 83.920 ;
    END
  END RBL[117]
  PIN RBL[125]
    ANTENNADIFFAREA 0.511400 ;
    PORT
      LAYER Metal4 ;
        RECT 18.270 88.400 27.535 89.400 ;
    END
  END RBL[125]
  PIN RBL[133]
    ANTENNADIFFAREA 0.511400 ;
    PORT
      LAYER Metal4 ;
        RECT 18.270 93.880 27.535 94.880 ;
    END
  END RBL[133]
  PIN RBL[141]
    ANTENNADIFFAREA 0.511400 ;
    PORT
      LAYER Metal4 ;
        RECT 18.270 99.360 27.535 100.360 ;
    END
  END RBL[141]
  PIN RBL[149]
    ANTENNADIFFAREA 0.511400 ;
    PORT
      LAYER Metal4 ;
        RECT 18.270 104.840 27.535 105.840 ;
    END
  END RBL[149]
  PIN RBL[157]
    ANTENNADIFFAREA 0.511400 ;
    PORT
      LAYER Metal4 ;
        RECT 18.270 110.320 27.535 111.320 ;
    END
  END RBL[157]
  PIN RBL[165]
    ANTENNADIFFAREA 0.511400 ;
    PORT
      LAYER Metal4 ;
        RECT 18.270 115.800 27.535 116.800 ;
    END
  END RBL[165]
  PIN RBL[173]
    ANTENNADIFFAREA 0.511400 ;
    PORT
      LAYER Metal4 ;
        RECT 18.270 121.280 27.535 122.280 ;
    END
  END RBL[173]
  PIN RBL[181]
    ANTENNADIFFAREA 0.511400 ;
    PORT
      LAYER Metal4 ;
        RECT 18.270 126.760 27.535 127.760 ;
    END
  END RBL[181]
  PIN RBL[189]
    ANTENNADIFFAREA 0.511400 ;
    PORT
      LAYER Metal4 ;
        RECT 18.270 132.240 27.535 133.240 ;
    END
  END RBL[189]
  PIN RBL[197]
    ANTENNADIFFAREA 0.511400 ;
    PORT
      LAYER Metal4 ;
        RECT 18.270 137.720 27.535 138.720 ;
    END
  END RBL[197]
  PIN RBL[205]
    ANTENNADIFFAREA 0.511400 ;
    PORT
      LAYER Metal4 ;
        RECT 18.270 143.200 27.535 144.200 ;
    END
  END RBL[205]
  PIN RBL[213]
    ANTENNADIFFAREA 0.511400 ;
    PORT
      LAYER Metal4 ;
        RECT 18.270 148.680 27.535 149.680 ;
    END
  END RBL[213]
  PIN RBL[221]
    ANTENNADIFFAREA 0.511400 ;
    PORT
      LAYER Metal4 ;
        RECT 18.270 154.160 27.535 155.160 ;
    END
  END RBL[221]
  PIN RBL[229]
    ANTENNADIFFAREA 0.511400 ;
    PORT
      LAYER Metal4 ;
        RECT 18.270 159.640 27.535 160.640 ;
    END
  END RBL[229]
  PIN RBL[237]
    ANTENNADIFFAREA 0.511400 ;
    PORT
      LAYER Metal4 ;
        RECT 18.270 165.120 27.535 166.120 ;
    END
  END RBL[237]
  PIN RBL[245]
    ANTENNADIFFAREA 0.511400 ;
    PORT
      LAYER Metal4 ;
        RECT 18.270 170.600 27.535 171.600 ;
    END
  END RBL[245]
  PIN RBL[253]
    ANTENNADIFFAREA 0.511400 ;
    PORT
      LAYER Metal4 ;
        RECT 18.270 176.080 27.535 177.080 ;
    END
  END RBL[253]
  PIN RBL[4]
    ANTENNADIFFAREA 0.511400 ;
    PORT
      LAYER Metal4 ;
        RECT 15.160 7.570 27.535 8.570 ;
    END
  END RBL[4]
  PIN RBL[12]
    ANTENNADIFFAREA 0.511400 ;
    PORT
      LAYER Metal4 ;
        RECT 15.160 13.050 27.535 14.050 ;
    END
  END RBL[12]
  PIN RBL[20]
    ANTENNADIFFAREA 0.511400 ;
    PORT
      LAYER Metal4 ;
        RECT 15.160 18.530 27.535 19.530 ;
    END
  END RBL[20]
  PIN RBL[28]
    ANTENNADIFFAREA 0.511400 ;
    PORT
      LAYER Metal4 ;
        RECT 15.160 24.010 27.535 25.010 ;
    END
  END RBL[28]
  PIN RBL[36]
    ANTENNADIFFAREA 0.511400 ;
    PORT
      LAYER Metal4 ;
        RECT 15.160 29.490 27.535 30.490 ;
    END
  END RBL[36]
  PIN RBL[44]
    ANTENNADIFFAREA 0.511400 ;
    PORT
      LAYER Metal4 ;
        RECT 15.160 34.970 27.535 35.970 ;
    END
  END RBL[44]
  PIN RBL[52]
    ANTENNADIFFAREA 0.511400 ;
    PORT
      LAYER Metal4 ;
        RECT 15.160 40.450 27.535 41.450 ;
    END
  END RBL[52]
  PIN RBL[60]
    ANTENNADIFFAREA 0.511400 ;
    PORT
      LAYER Metal4 ;
        RECT 15.160 45.930 27.535 46.930 ;
    END
  END RBL[60]
  PIN RBL[68]
    ANTENNADIFFAREA 0.511400 ;
    PORT
      LAYER Metal4 ;
        RECT 15.160 51.410 27.535 52.410 ;
    END
  END RBL[68]
  PIN RBL[76]
    ANTENNADIFFAREA 0.511400 ;
    PORT
      LAYER Metal4 ;
        RECT 15.160 56.890 27.535 57.890 ;
    END
  END RBL[76]
  PIN RBL[84]
    ANTENNADIFFAREA 0.511400 ;
    PORT
      LAYER Metal4 ;
        RECT 15.160 62.370 27.535 63.370 ;
    END
  END RBL[84]
  PIN RBL[92]
    ANTENNADIFFAREA 0.511400 ;
    PORT
      LAYER Metal4 ;
        RECT 15.160 67.850 27.535 68.850 ;
    END
  END RBL[92]
  PIN RBL[100]
    ANTENNADIFFAREA 0.511400 ;
    PORT
      LAYER Metal4 ;
        RECT 15.160 73.330 27.535 74.330 ;
    END
  END RBL[100]
  PIN RBL[108]
    ANTENNADIFFAREA 0.511400 ;
    PORT
      LAYER Metal4 ;
        RECT 15.160 78.810 27.535 79.810 ;
    END
  END RBL[108]
  PIN RBL[116]
    ANTENNADIFFAREA 0.511400 ;
    PORT
      LAYER Metal4 ;
        RECT 15.160 84.290 27.535 85.290 ;
    END
  END RBL[116]
  PIN RBL[124]
    ANTENNADIFFAREA 0.511400 ;
    PORT
      LAYER Metal4 ;
        RECT 15.160 89.770 27.535 90.770 ;
    END
  END RBL[124]
  PIN RBL[132]
    ANTENNADIFFAREA 0.511400 ;
    PORT
      LAYER Metal4 ;
        RECT 15.160 95.250 27.535 96.250 ;
    END
  END RBL[132]
  PIN RBL[140]
    ANTENNADIFFAREA 0.511400 ;
    PORT
      LAYER Metal4 ;
        RECT 15.160 100.730 27.535 101.730 ;
    END
  END RBL[140]
  PIN RBL[148]
    ANTENNADIFFAREA 0.511400 ;
    PORT
      LAYER Metal4 ;
        RECT 15.160 106.210 27.535 107.210 ;
    END
  END RBL[148]
  PIN RBL[156]
    ANTENNADIFFAREA 0.511400 ;
    PORT
      LAYER Metal4 ;
        RECT 15.160 111.690 27.535 112.690 ;
    END
  END RBL[156]
  PIN RBL[164]
    ANTENNADIFFAREA 0.511400 ;
    PORT
      LAYER Metal4 ;
        RECT 15.160 117.170 27.535 118.170 ;
    END
  END RBL[164]
  PIN RBL[172]
    ANTENNADIFFAREA 0.511400 ;
    PORT
      LAYER Metal4 ;
        RECT 15.160 122.650 27.535 123.650 ;
    END
  END RBL[172]
  PIN RBL[180]
    ANTENNADIFFAREA 0.511400 ;
    PORT
      LAYER Metal4 ;
        RECT 15.160 128.130 27.535 129.130 ;
    END
  END RBL[180]
  PIN RBL[188]
    ANTENNADIFFAREA 0.511400 ;
    PORT
      LAYER Metal4 ;
        RECT 15.160 133.610 27.535 134.610 ;
    END
  END RBL[188]
  PIN RBL[196]
    ANTENNADIFFAREA 0.511400 ;
    PORT
      LAYER Metal4 ;
        RECT 15.160 139.090 27.535 140.090 ;
    END
  END RBL[196]
  PIN RBL[204]
    ANTENNADIFFAREA 0.511400 ;
    PORT
      LAYER Metal4 ;
        RECT 15.160 144.570 27.535 145.570 ;
    END
  END RBL[204]
  PIN RBL[212]
    ANTENNADIFFAREA 0.511400 ;
    PORT
      LAYER Metal4 ;
        RECT 15.160 150.050 27.535 151.050 ;
    END
  END RBL[212]
  PIN RBL[220]
    ANTENNADIFFAREA 0.511400 ;
    PORT
      LAYER Metal4 ;
        RECT 15.160 155.530 27.535 156.530 ;
    END
  END RBL[220]
  PIN RBL[228]
    ANTENNADIFFAREA 0.511400 ;
    PORT
      LAYER Metal4 ;
        RECT 15.160 161.010 27.535 162.010 ;
    END
  END RBL[228]
  PIN RBL[236]
    ANTENNADIFFAREA 0.511400 ;
    PORT
      LAYER Metal4 ;
        RECT 15.160 166.490 27.535 167.490 ;
    END
  END RBL[236]
  PIN RBL[244]
    ANTENNADIFFAREA 0.511400 ;
    PORT
      LAYER Metal4 ;
        RECT 15.160 171.970 27.535 172.970 ;
    END
  END RBL[244]
  PIN RBL[252]
    ANTENNADIFFAREA 0.511400 ;
    PORT
      LAYER Metal4 ;
        RECT 15.160 177.450 27.535 178.450 ;
    END
  END RBL[252]
  PIN RBL[1]
    ANTENNADIFFAREA 0.511400 ;
    PORT
      LAYER Metal4 ;
        RECT -2.800 4.830 6.110 5.830 ;
    END
  END RBL[1]
  PIN RBL[9]
    ANTENNADIFFAREA 0.511400 ;
    PORT
      LAYER Metal4 ;
        RECT -2.800 10.310 6.110 11.310 ;
    END
  END RBL[9]
  PIN RBL[17]
    ANTENNADIFFAREA 0.511400 ;
    PORT
      LAYER Metal4 ;
        RECT -2.800 15.790 6.110 16.790 ;
    END
  END RBL[17]
  PIN RBL[25]
    ANTENNADIFFAREA 0.511400 ;
    PORT
      LAYER Metal4 ;
        RECT -2.800 21.270 6.110 22.270 ;
    END
  END RBL[25]
  PIN RBL[33]
    ANTENNADIFFAREA 0.511400 ;
    PORT
      LAYER Metal4 ;
        RECT -2.800 26.750 6.110 27.750 ;
    END
  END RBL[33]
  PIN RBL[41]
    ANTENNADIFFAREA 0.511400 ;
    PORT
      LAYER Metal4 ;
        RECT -2.800 32.230 6.110 33.230 ;
    END
  END RBL[41]
  PIN RBL[49]
    ANTENNADIFFAREA 0.511400 ;
    PORT
      LAYER Metal4 ;
        RECT -2.800 37.710 6.110 38.710 ;
    END
  END RBL[49]
  PIN RBL[57]
    ANTENNADIFFAREA 0.511400 ;
    PORT
      LAYER Metal4 ;
        RECT -2.800 43.190 6.110 44.190 ;
    END
  END RBL[57]
  PIN RBL[65]
    ANTENNADIFFAREA 0.511400 ;
    PORT
      LAYER Metal4 ;
        RECT -2.800 48.670 6.110 49.670 ;
    END
  END RBL[65]
  PIN RBL[73]
    ANTENNADIFFAREA 0.511400 ;
    PORT
      LAYER Metal4 ;
        RECT -2.800 54.150 6.110 55.150 ;
    END
  END RBL[73]
  PIN RBL[81]
    ANTENNADIFFAREA 0.511400 ;
    PORT
      LAYER Metal4 ;
        RECT -2.800 59.630 6.110 60.630 ;
    END
  END RBL[81]
  PIN RBL[89]
    ANTENNADIFFAREA 0.511400 ;
    PORT
      LAYER Metal4 ;
        RECT -2.800 65.110 6.110 66.110 ;
    END
  END RBL[89]
  PIN RBL[97]
    ANTENNADIFFAREA 0.511400 ;
    PORT
      LAYER Metal4 ;
        RECT -2.800 70.590 6.110 71.590 ;
    END
  END RBL[97]
  PIN RBL[105]
    ANTENNADIFFAREA 0.511400 ;
    PORT
      LAYER Metal4 ;
        RECT -2.800 76.070 6.110 77.070 ;
    END
  END RBL[105]
  PIN RBL[113]
    ANTENNADIFFAREA 0.511400 ;
    PORT
      LAYER Metal4 ;
        RECT -2.800 81.550 6.110 82.550 ;
    END
  END RBL[113]
  PIN RBL[121]
    ANTENNADIFFAREA 0.511400 ;
    PORT
      LAYER Metal4 ;
        RECT -2.800 87.030 6.110 88.030 ;
    END
  END RBL[121]
  PIN RBL[129]
    ANTENNADIFFAREA 0.511400 ;
    PORT
      LAYER Metal4 ;
        RECT -2.800 92.510 6.110 93.510 ;
    END
  END RBL[129]
  PIN RBL[137]
    ANTENNADIFFAREA 0.511400 ;
    PORT
      LAYER Metal4 ;
        RECT -2.800 97.990 6.110 98.990 ;
    END
  END RBL[137]
  PIN RBL[145]
    ANTENNADIFFAREA 0.511400 ;
    PORT
      LAYER Metal4 ;
        RECT -2.800 103.470 6.110 104.470 ;
    END
  END RBL[145]
  PIN RBL[153]
    ANTENNADIFFAREA 0.511400 ;
    PORT
      LAYER Metal4 ;
        RECT -2.800 108.950 6.110 109.950 ;
    END
  END RBL[153]
  PIN RBL[161]
    ANTENNADIFFAREA 0.511400 ;
    PORT
      LAYER Metal4 ;
        RECT -2.800 114.430 6.110 115.430 ;
    END
  END RBL[161]
  PIN RBL[169]
    ANTENNADIFFAREA 0.511400 ;
    PORT
      LAYER Metal4 ;
        RECT -2.800 119.910 6.110 120.910 ;
    END
  END RBL[169]
  PIN RBL[177]
    ANTENNADIFFAREA 0.511400 ;
    PORT
      LAYER Metal4 ;
        RECT -2.800 125.390 6.110 126.390 ;
    END
  END RBL[177]
  PIN RBL[185]
    ANTENNADIFFAREA 0.511400 ;
    PORT
      LAYER Metal4 ;
        RECT -2.800 130.870 6.110 131.870 ;
    END
  END RBL[185]
  PIN RBL[193]
    ANTENNADIFFAREA 0.511400 ;
    PORT
      LAYER Metal4 ;
        RECT -2.800 136.350 6.110 137.350 ;
    END
  END RBL[193]
  PIN RBL[201]
    ANTENNADIFFAREA 0.511400 ;
    PORT
      LAYER Metal4 ;
        RECT -2.800 141.830 6.110 142.830 ;
    END
  END RBL[201]
  PIN RBL[209]
    ANTENNADIFFAREA 0.511400 ;
    PORT
      LAYER Metal4 ;
        RECT -2.800 147.310 6.110 148.310 ;
    END
  END RBL[209]
  PIN RBL[217]
    ANTENNADIFFAREA 0.511400 ;
    PORT
      LAYER Metal4 ;
        RECT -2.800 152.790 6.110 153.790 ;
    END
  END RBL[217]
  PIN RBL[225]
    ANTENNADIFFAREA 0.511400 ;
    PORT
      LAYER Metal4 ;
        RECT -2.800 158.270 6.110 159.270 ;
    END
  END RBL[225]
  PIN RBL[233]
    ANTENNADIFFAREA 0.511400 ;
    PORT
      LAYER Metal4 ;
        RECT -2.800 163.750 6.110 164.750 ;
    END
  END RBL[233]
  PIN RBL[241]
    ANTENNADIFFAREA 0.511400 ;
    PORT
      LAYER Metal4 ;
        RECT -2.800 169.230 6.110 170.230 ;
    END
  END RBL[241]
  PIN RBL[249]
    ANTENNADIFFAREA 0.511400 ;
    PORT
      LAYER Metal4 ;
        RECT -2.800 174.710 6.110 175.710 ;
    END
  END RBL[249]
  PIN RBL[2]
    ANTENNADIFFAREA 0.511400 ;
    PORT
      LAYER Metal4 ;
        RECT -2.800 6.200 9.220 7.200 ;
    END
  END RBL[2]
  PIN RBL[10]
    ANTENNADIFFAREA 0.511400 ;
    PORT
      LAYER Metal4 ;
        RECT -2.800 11.680 9.220 12.680 ;
    END
  END RBL[10]
  PIN RBL[18]
    ANTENNADIFFAREA 0.511400 ;
    PORT
      LAYER Metal4 ;
        RECT -2.800 17.160 9.220 18.160 ;
    END
  END RBL[18]
  PIN RBL[26]
    ANTENNADIFFAREA 0.511400 ;
    PORT
      LAYER Metal4 ;
        RECT -2.800 22.640 9.220 23.640 ;
    END
  END RBL[26]
  PIN RBL[34]
    ANTENNADIFFAREA 0.511400 ;
    PORT
      LAYER Metal4 ;
        RECT -2.800 28.120 9.220 29.120 ;
    END
  END RBL[34]
  PIN RBL[42]
    ANTENNADIFFAREA 0.511400 ;
    PORT
      LAYER Metal4 ;
        RECT -2.800 33.600 9.220 34.600 ;
    END
  END RBL[42]
  PIN RBL[50]
    ANTENNADIFFAREA 0.511400 ;
    PORT
      LAYER Metal4 ;
        RECT -2.800 39.080 9.220 40.080 ;
    END
  END RBL[50]
  PIN RBL[58]
    ANTENNADIFFAREA 0.511400 ;
    PORT
      LAYER Metal4 ;
        RECT -2.800 44.560 9.220 45.560 ;
    END
  END RBL[58]
  PIN RBL[66]
    ANTENNADIFFAREA 0.511400 ;
    PORT
      LAYER Metal4 ;
        RECT -2.800 50.040 9.220 51.040 ;
    END
  END RBL[66]
  PIN RBL[74]
    ANTENNADIFFAREA 0.511400 ;
    PORT
      LAYER Metal4 ;
        RECT -2.800 55.520 9.220 56.520 ;
    END
  END RBL[74]
  PIN RBL[82]
    ANTENNADIFFAREA 0.511400 ;
    PORT
      LAYER Metal4 ;
        RECT -2.800 61.000 9.220 62.000 ;
    END
  END RBL[82]
  PIN RBL[90]
    ANTENNADIFFAREA 0.511400 ;
    PORT
      LAYER Metal4 ;
        RECT -2.800 66.480 9.220 67.480 ;
    END
  END RBL[90]
  PIN RBL[98]
    ANTENNADIFFAREA 0.511400 ;
    PORT
      LAYER Metal4 ;
        RECT -2.800 71.960 9.220 72.960 ;
    END
  END RBL[98]
  PIN RBL[106]
    ANTENNADIFFAREA 0.511400 ;
    PORT
      LAYER Metal4 ;
        RECT -2.800 77.440 9.220 78.440 ;
    END
  END RBL[106]
  PIN RBL[114]
    ANTENNADIFFAREA 0.511400 ;
    PORT
      LAYER Metal4 ;
        RECT -2.800 82.920 9.220 83.920 ;
    END
  END RBL[114]
  PIN RBL[122]
    ANTENNADIFFAREA 0.511400 ;
    PORT
      LAYER Metal4 ;
        RECT -2.800 88.400 9.220 89.400 ;
    END
  END RBL[122]
  PIN RBL[130]
    ANTENNADIFFAREA 0.511400 ;
    PORT
      LAYER Metal4 ;
        RECT -2.800 93.880 9.220 94.880 ;
    END
  END RBL[130]
  PIN RBL[138]
    ANTENNADIFFAREA 0.511400 ;
    PORT
      LAYER Metal4 ;
        RECT -2.800 99.360 9.220 100.360 ;
    END
  END RBL[138]
  PIN RBL[146]
    ANTENNADIFFAREA 0.511400 ;
    PORT
      LAYER Metal4 ;
        RECT -2.800 104.840 9.220 105.840 ;
    END
  END RBL[146]
  PIN RBL[154]
    ANTENNADIFFAREA 0.511400 ;
    PORT
      LAYER Metal4 ;
        RECT -2.800 110.320 9.220 111.320 ;
    END
  END RBL[154]
  PIN RBL[162]
    ANTENNADIFFAREA 0.511400 ;
    PORT
      LAYER Metal4 ;
        RECT -2.800 115.800 9.220 116.800 ;
    END
  END RBL[162]
  PIN RBL[170]
    ANTENNADIFFAREA 0.511400 ;
    PORT
      LAYER Metal4 ;
        RECT -2.800 121.280 9.220 122.280 ;
    END
  END RBL[170]
  PIN RBL[178]
    ANTENNADIFFAREA 0.511400 ;
    PORT
      LAYER Metal4 ;
        RECT -2.800 126.760 9.220 127.760 ;
    END
  END RBL[178]
  PIN RBL[186]
    ANTENNADIFFAREA 0.511400 ;
    PORT
      LAYER Metal4 ;
        RECT -2.800 132.240 9.220 133.240 ;
    END
  END RBL[186]
  PIN RBL[194]
    ANTENNADIFFAREA 0.511400 ;
    PORT
      LAYER Metal4 ;
        RECT -2.800 137.720 9.220 138.720 ;
    END
  END RBL[194]
  PIN RBL[202]
    ANTENNADIFFAREA 0.511400 ;
    PORT
      LAYER Metal4 ;
        RECT -2.800 143.200 9.220 144.200 ;
    END
  END RBL[202]
  PIN RBL[210]
    ANTENNADIFFAREA 0.511400 ;
    PORT
      LAYER Metal4 ;
        RECT -2.800 148.680 9.220 149.680 ;
    END
  END RBL[210]
  PIN RBL[218]
    ANTENNADIFFAREA 0.511400 ;
    PORT
      LAYER Metal4 ;
        RECT -2.800 154.160 9.220 155.160 ;
    END
  END RBL[218]
  PIN RBL[226]
    ANTENNADIFFAREA 0.511400 ;
    PORT
      LAYER Metal4 ;
        RECT -2.800 159.640 9.220 160.640 ;
    END
  END RBL[226]
  PIN RBL[234]
    ANTENNADIFFAREA 0.511400 ;
    PORT
      LAYER Metal4 ;
        RECT -2.800 165.120 9.220 166.120 ;
    END
  END RBL[234]
  PIN RBL[242]
    ANTENNADIFFAREA 0.511400 ;
    PORT
      LAYER Metal4 ;
        RECT -2.800 170.600 9.220 171.600 ;
    END
  END RBL[242]
  PIN RBL[250]
    ANTENNADIFFAREA 0.511400 ;
    PORT
      LAYER Metal4 ;
        RECT -2.800 176.080 9.220 177.080 ;
    END
  END RBL[250]
  PIN RBL[3]
    ANTENNADIFFAREA 0.511400 ;
    PORT
      LAYER Metal4 ;
        RECT -2.800 7.570 12.330 8.570 ;
    END
  END RBL[3]
  PIN RBL[11]
    ANTENNADIFFAREA 0.511400 ;
    PORT
      LAYER Metal4 ;
        RECT -2.800 13.050 12.330 14.050 ;
    END
  END RBL[11]
  PIN RBL[19]
    ANTENNADIFFAREA 0.511400 ;
    PORT
      LAYER Metal4 ;
        RECT -2.800 18.530 12.330 19.530 ;
    END
  END RBL[19]
  PIN RBL[27]
    ANTENNADIFFAREA 0.511400 ;
    PORT
      LAYER Metal4 ;
        RECT -2.800 24.010 12.330 25.010 ;
    END
  END RBL[27]
  PIN RBL[35]
    ANTENNADIFFAREA 0.511400 ;
    PORT
      LAYER Metal4 ;
        RECT -2.800 29.490 12.330 30.490 ;
    END
  END RBL[35]
  PIN RBL[43]
    ANTENNADIFFAREA 0.511400 ;
    PORT
      LAYER Metal4 ;
        RECT -2.800 34.970 12.330 35.970 ;
    END
  END RBL[43]
  PIN RBL[51]
    ANTENNADIFFAREA 0.511400 ;
    PORT
      LAYER Metal4 ;
        RECT -2.800 40.450 12.330 41.450 ;
    END
  END RBL[51]
  PIN RBL[59]
    ANTENNADIFFAREA 0.511400 ;
    PORT
      LAYER Metal4 ;
        RECT -2.800 45.930 12.330 46.930 ;
    END
  END RBL[59]
  PIN RBL[67]
    ANTENNADIFFAREA 0.511400 ;
    PORT
      LAYER Metal4 ;
        RECT -2.800 51.410 12.330 52.410 ;
    END
  END RBL[67]
  PIN RBL[75]
    ANTENNADIFFAREA 0.511400 ;
    PORT
      LAYER Metal4 ;
        RECT -2.800 56.890 12.330 57.890 ;
    END
  END RBL[75]
  PIN RBL[83]
    ANTENNADIFFAREA 0.511400 ;
    PORT
      LAYER Metal4 ;
        RECT -2.800 62.370 12.330 63.370 ;
    END
  END RBL[83]
  PIN RBL[91]
    ANTENNADIFFAREA 0.511400 ;
    PORT
      LAYER Metal4 ;
        RECT -2.800 67.850 12.330 68.850 ;
    END
  END RBL[91]
  PIN RBL[99]
    ANTENNADIFFAREA 0.511400 ;
    PORT
      LAYER Metal4 ;
        RECT -2.800 73.330 12.330 74.330 ;
    END
  END RBL[99]
  PIN RBL[107]
    ANTENNADIFFAREA 0.511400 ;
    PORT
      LAYER Metal4 ;
        RECT -2.800 78.810 12.330 79.810 ;
    END
  END RBL[107]
  PIN RBL[115]
    ANTENNADIFFAREA 0.511400 ;
    PORT
      LAYER Metal4 ;
        RECT -2.800 84.290 12.330 85.290 ;
    END
  END RBL[115]
  PIN RBL[123]
    ANTENNADIFFAREA 0.511400 ;
    PORT
      LAYER Metal4 ;
        RECT -2.800 89.770 12.330 90.770 ;
    END
  END RBL[123]
  PIN RBL[131]
    ANTENNADIFFAREA 0.511400 ;
    PORT
      LAYER Metal4 ;
        RECT -2.800 95.250 12.330 96.250 ;
    END
  END RBL[131]
  PIN RBL[139]
    ANTENNADIFFAREA 0.511400 ;
    PORT
      LAYER Metal4 ;
        RECT -2.800 100.730 12.330 101.730 ;
    END
  END RBL[139]
  PIN RBL[147]
    ANTENNADIFFAREA 0.511400 ;
    PORT
      LAYER Metal4 ;
        RECT -2.800 106.210 12.330 107.210 ;
    END
  END RBL[147]
  PIN RBL[155]
    ANTENNADIFFAREA 0.511400 ;
    PORT
      LAYER Metal4 ;
        RECT -2.800 111.690 12.330 112.690 ;
    END
  END RBL[155]
  PIN RBL[163]
    ANTENNADIFFAREA 0.511400 ;
    PORT
      LAYER Metal4 ;
        RECT -2.800 117.170 12.330 118.170 ;
    END
  END RBL[163]
  PIN RBL[171]
    ANTENNADIFFAREA 0.511400 ;
    PORT
      LAYER Metal4 ;
        RECT -2.800 122.650 12.330 123.650 ;
    END
  END RBL[171]
  PIN RBL[179]
    ANTENNADIFFAREA 0.511400 ;
    PORT
      LAYER Metal4 ;
        RECT -2.800 128.130 12.330 129.130 ;
    END
  END RBL[179]
  PIN RBL[187]
    ANTENNADIFFAREA 0.511400 ;
    PORT
      LAYER Metal4 ;
        RECT -2.800 133.610 12.330 134.610 ;
    END
  END RBL[187]
  PIN RBL[195]
    ANTENNADIFFAREA 0.511400 ;
    PORT
      LAYER Metal4 ;
        RECT -2.800 139.090 12.330 140.090 ;
    END
  END RBL[195]
  PIN RBL[203]
    ANTENNADIFFAREA 0.511400 ;
    PORT
      LAYER Metal4 ;
        RECT -2.800 144.570 12.330 145.570 ;
    END
  END RBL[203]
  PIN RBL[211]
    ANTENNADIFFAREA 0.511400 ;
    PORT
      LAYER Metal4 ;
        RECT -2.800 150.050 12.330 151.050 ;
    END
  END RBL[211]
  PIN RBL[219]
    ANTENNADIFFAREA 0.511400 ;
    PORT
      LAYER Metal4 ;
        RECT -2.800 155.530 12.330 156.530 ;
    END
  END RBL[219]
  PIN RBL[227]
    ANTENNADIFFAREA 0.511400 ;
    PORT
      LAYER Metal4 ;
        RECT -2.800 161.010 12.330 162.010 ;
    END
  END RBL[227]
  PIN RBL[235]
    ANTENNADIFFAREA 0.511400 ;
    PORT
      LAYER Metal4 ;
        RECT -2.800 166.490 12.330 167.490 ;
    END
  END RBL[235]
  PIN RBL[243]
    ANTENNADIFFAREA 0.511400 ;
    PORT
      LAYER Metal4 ;
        RECT -2.800 171.970 12.330 172.970 ;
    END
  END RBL[243]
  PIN RBL[251]
    ANTENNADIFFAREA 0.511400 ;
    PORT
      LAYER Metal4 ;
        RECT -2.800 177.450 12.330 178.450 ;
    END
  END RBL[251]
  OBS
      LAYER Nwell ;
        RECT -1.420 0.000 26.300 175.360 ;
      LAYER Metal1 ;
        RECT -1.300 0.000 26.180 175.360 ;
      LAYER Metal2 ;
        RECT -1.325 172.870 26.170 174.875 ;
        RECT -2.875 171.085 27.755 172.870 ;
        RECT -0.920 169.660 25.875 171.085 ;
        RECT -1.325 167.390 26.170 169.660 ;
        RECT -2.875 165.605 27.755 167.390 ;
        RECT -0.920 164.180 25.875 165.605 ;
        RECT -1.325 161.910 26.170 164.180 ;
        RECT -2.875 160.125 27.755 161.910 ;
        RECT -0.920 158.700 25.875 160.125 ;
        RECT -1.325 156.430 26.170 158.700 ;
        RECT -2.875 154.645 27.755 156.430 ;
        RECT -0.920 153.220 25.875 154.645 ;
        RECT -1.325 150.950 26.170 153.220 ;
        RECT -2.875 149.165 27.755 150.950 ;
        RECT -0.920 147.740 25.875 149.165 ;
        RECT -1.325 145.470 26.170 147.740 ;
        RECT -2.875 143.685 27.755 145.470 ;
        RECT -0.920 142.260 25.875 143.685 ;
        RECT -1.325 139.990 26.170 142.260 ;
        RECT -2.875 138.205 27.755 139.990 ;
        RECT -0.920 136.780 25.875 138.205 ;
        RECT -1.325 134.510 26.170 136.780 ;
        RECT -2.875 132.725 27.755 134.510 ;
        RECT -0.920 131.300 25.875 132.725 ;
        RECT -1.325 129.030 26.170 131.300 ;
        RECT -2.875 127.245 27.755 129.030 ;
        RECT -0.920 125.820 25.875 127.245 ;
        RECT -1.325 123.550 26.170 125.820 ;
        RECT -2.875 121.765 27.755 123.550 ;
        RECT -0.920 120.340 25.875 121.765 ;
        RECT -1.325 118.070 26.170 120.340 ;
        RECT -2.875 116.285 27.755 118.070 ;
        RECT -0.920 114.860 25.875 116.285 ;
        RECT -1.325 112.590 26.170 114.860 ;
        RECT -2.875 110.805 27.755 112.590 ;
        RECT -0.920 109.380 25.875 110.805 ;
        RECT -1.325 107.110 26.170 109.380 ;
        RECT -2.875 105.325 27.755 107.110 ;
        RECT -0.920 103.900 25.875 105.325 ;
        RECT -1.325 101.630 26.170 103.900 ;
        RECT -2.875 99.845 27.755 101.630 ;
        RECT -0.920 98.420 25.875 99.845 ;
        RECT -1.325 96.150 26.170 98.420 ;
        RECT -2.875 94.365 27.755 96.150 ;
        RECT -0.920 92.940 25.875 94.365 ;
        RECT -1.325 90.670 26.170 92.940 ;
        RECT -2.875 88.885 27.755 90.670 ;
        RECT -0.920 87.460 25.875 88.885 ;
        RECT -1.325 85.190 26.170 87.460 ;
        RECT -2.875 83.405 27.755 85.190 ;
        RECT -0.920 81.980 25.875 83.405 ;
        RECT -1.325 79.710 26.170 81.980 ;
        RECT -2.875 77.925 27.755 79.710 ;
        RECT -0.920 76.500 25.875 77.925 ;
        RECT -1.325 74.230 26.170 76.500 ;
        RECT -2.875 72.445 27.755 74.230 ;
        RECT -0.920 71.020 25.875 72.445 ;
        RECT -1.325 68.750 26.170 71.020 ;
        RECT -2.875 66.965 27.755 68.750 ;
        RECT -0.920 65.540 25.875 66.965 ;
        RECT -1.325 63.270 26.170 65.540 ;
        RECT -2.875 61.485 27.755 63.270 ;
        RECT -0.920 60.060 25.875 61.485 ;
        RECT -1.325 57.790 26.170 60.060 ;
        RECT -2.875 56.005 27.755 57.790 ;
        RECT -0.920 54.580 25.875 56.005 ;
        RECT -1.325 52.310 26.170 54.580 ;
        RECT -2.875 50.525 27.755 52.310 ;
        RECT -0.920 49.100 25.875 50.525 ;
        RECT -1.325 46.830 26.170 49.100 ;
        RECT -2.875 45.045 27.755 46.830 ;
        RECT -0.920 43.620 25.875 45.045 ;
        RECT -1.325 41.350 26.170 43.620 ;
        RECT -2.875 39.565 27.755 41.350 ;
        RECT -0.920 38.140 25.875 39.565 ;
        RECT -1.325 35.870 26.170 38.140 ;
        RECT -2.875 34.085 27.755 35.870 ;
        RECT -0.920 32.660 25.875 34.085 ;
        RECT -1.325 30.390 26.170 32.660 ;
        RECT -2.875 28.605 27.755 30.390 ;
        RECT -0.920 27.180 25.875 28.605 ;
        RECT -1.325 24.910 26.170 27.180 ;
        RECT -2.875 23.125 27.755 24.910 ;
        RECT -0.920 21.700 25.875 23.125 ;
        RECT -1.325 19.430 26.170 21.700 ;
        RECT -2.875 17.645 27.755 19.430 ;
        RECT -0.920 16.220 25.875 17.645 ;
        RECT -1.325 13.950 26.170 16.220 ;
        RECT -2.875 12.165 27.755 13.950 ;
        RECT -0.920 10.740 25.875 12.165 ;
        RECT -1.325 8.470 26.170 10.740 ;
        RECT -2.875 6.685 27.755 8.470 ;
        RECT -0.920 5.260 25.875 6.685 ;
        RECT -1.325 2.990 26.170 5.260 ;
        RECT -2.875 1.205 27.755 2.990 ;
        RECT -0.920 0.030 25.875 1.205 ;
      LAYER Metal3 ;
        RECT 2.790 175.560 3.085 175.860 ;
        RECT 5.900 175.560 6.195 175.860 ;
        RECT 9.010 175.560 9.305 175.860 ;
        RECT 12.120 175.560 12.415 175.860 ;
        RECT 15.230 175.560 15.525 175.860 ;
        RECT 18.340 175.560 18.635 175.860 ;
        RECT 21.450 175.560 21.745 175.860 ;
        RECT 24.560 175.560 24.835 175.860 ;
        RECT 1.535 175.555 3.085 175.560 ;
        RECT 4.645 175.555 6.195 175.560 ;
        RECT 7.755 175.555 9.305 175.560 ;
        RECT 10.865 175.555 12.415 175.560 ;
        RECT 13.975 175.555 15.525 175.560 ;
        RECT 17.085 175.555 18.635 175.560 ;
        RECT 20.195 175.555 21.745 175.560 ;
        RECT 23.305 175.555 24.835 175.560 ;
        RECT 0.170 -0.195 24.835 175.555 ;
        RECT 0.170 -0.200 1.220 -0.195 ;
        RECT 2.780 -0.200 4.340 -0.195 ;
        RECT 5.900 -0.200 7.450 -0.195 ;
        RECT 9.010 -0.200 10.560 -0.195 ;
        RECT 12.120 -0.200 13.670 -0.195 ;
        RECT 15.230 -0.200 16.780 -0.195 ;
        RECT 18.340 -0.200 19.890 -0.195 ;
        RECT 21.450 -0.200 23.000 -0.195 ;
        RECT 2.780 -0.500 3.070 -0.200 ;
        RECT 5.900 -0.500 6.180 -0.200 ;
        RECT 9.010 -0.500 9.290 -0.200 ;
        RECT 12.120 -0.500 12.400 -0.200 ;
        RECT 15.230 -0.500 15.510 -0.200 ;
        RECT 18.340 -0.500 18.620 -0.200 ;
        RECT 21.450 -0.500 21.730 -0.200 ;
        RECT 24.560 -0.500 24.835 -0.195 ;
      LAYER Metal4 ;
        RECT 12.630 177.150 14.860 177.450 ;
        RECT 9.520 175.780 17.970 177.150 ;
        RECT 6.410 174.410 21.080 175.780 ;
        RECT 3.010 173.270 22.380 174.410 ;
        RECT 12.630 171.670 14.860 173.270 ;
        RECT 9.520 170.300 17.970 171.670 ;
        RECT 6.410 168.930 21.080 170.300 ;
        RECT 3.010 167.790 22.380 168.930 ;
        RECT 12.630 166.190 14.860 167.790 ;
        RECT 9.520 164.820 17.970 166.190 ;
        RECT 6.410 163.450 21.080 164.820 ;
        RECT 3.010 162.310 22.380 163.450 ;
        RECT 12.630 160.710 14.860 162.310 ;
        RECT 9.520 159.340 17.970 160.710 ;
        RECT 6.410 157.970 21.080 159.340 ;
        RECT 3.010 156.830 22.380 157.970 ;
        RECT 12.630 155.230 14.860 156.830 ;
        RECT 9.520 153.860 17.970 155.230 ;
        RECT 6.410 152.490 21.080 153.860 ;
        RECT 3.010 151.350 22.380 152.490 ;
        RECT 12.630 149.750 14.860 151.350 ;
        RECT 9.520 148.380 17.970 149.750 ;
        RECT 6.410 147.010 21.080 148.380 ;
        RECT 3.010 145.870 22.380 147.010 ;
        RECT 12.630 144.270 14.860 145.870 ;
        RECT 9.520 142.900 17.970 144.270 ;
        RECT 6.410 141.530 21.080 142.900 ;
        RECT 3.010 140.390 22.380 141.530 ;
        RECT 12.630 138.790 14.860 140.390 ;
        RECT 9.520 137.420 17.970 138.790 ;
        RECT 6.410 136.050 21.080 137.420 ;
        RECT 3.010 134.910 22.380 136.050 ;
        RECT 12.630 133.310 14.860 134.910 ;
        RECT 9.520 131.940 17.970 133.310 ;
        RECT 6.410 130.570 21.080 131.940 ;
        RECT 3.010 129.430 22.380 130.570 ;
        RECT 12.630 127.830 14.860 129.430 ;
        RECT 9.520 126.460 17.970 127.830 ;
        RECT 6.410 125.090 21.080 126.460 ;
        RECT 3.010 123.950 22.380 125.090 ;
        RECT 12.630 122.350 14.860 123.950 ;
        RECT 9.520 120.980 17.970 122.350 ;
        RECT 6.410 119.610 21.080 120.980 ;
        RECT 3.010 118.470 22.380 119.610 ;
        RECT 12.630 116.870 14.860 118.470 ;
        RECT 9.520 115.500 17.970 116.870 ;
        RECT 6.410 114.130 21.080 115.500 ;
        RECT 3.010 112.990 22.380 114.130 ;
        RECT 12.630 111.390 14.860 112.990 ;
        RECT 9.520 110.020 17.970 111.390 ;
        RECT 6.410 108.650 21.080 110.020 ;
        RECT 3.010 107.510 22.380 108.650 ;
        RECT 12.630 105.910 14.860 107.510 ;
        RECT 9.520 104.540 17.970 105.910 ;
        RECT 6.410 103.170 21.080 104.540 ;
        RECT 3.010 102.030 22.380 103.170 ;
        RECT 12.630 100.430 14.860 102.030 ;
        RECT 9.520 99.060 17.970 100.430 ;
        RECT 6.410 97.690 21.080 99.060 ;
        RECT 3.010 96.550 22.380 97.690 ;
        RECT 12.630 94.950 14.860 96.550 ;
        RECT 9.520 93.580 17.970 94.950 ;
        RECT 6.410 92.210 21.080 93.580 ;
        RECT 3.010 91.070 22.380 92.210 ;
        RECT 12.630 89.470 14.860 91.070 ;
        RECT 9.520 88.100 17.970 89.470 ;
        RECT 6.410 86.730 21.080 88.100 ;
        RECT 3.010 85.590 22.380 86.730 ;
        RECT 12.630 83.990 14.860 85.590 ;
        RECT 9.520 82.620 17.970 83.990 ;
        RECT 6.410 81.250 21.080 82.620 ;
        RECT 3.010 80.110 22.380 81.250 ;
        RECT 12.630 78.510 14.860 80.110 ;
        RECT 9.520 77.140 17.970 78.510 ;
        RECT 6.410 75.770 21.080 77.140 ;
        RECT 3.010 74.630 22.380 75.770 ;
        RECT 12.630 73.030 14.860 74.630 ;
        RECT 9.520 71.660 17.970 73.030 ;
        RECT 6.410 70.290 21.080 71.660 ;
        RECT 3.010 69.150 22.380 70.290 ;
        RECT 12.630 67.550 14.860 69.150 ;
        RECT 9.520 66.180 17.970 67.550 ;
        RECT 6.410 64.810 21.080 66.180 ;
        RECT 3.010 63.670 22.380 64.810 ;
        RECT 12.630 62.070 14.860 63.670 ;
        RECT 9.520 60.700 17.970 62.070 ;
        RECT 6.410 59.330 21.080 60.700 ;
        RECT 3.010 58.190 22.380 59.330 ;
        RECT 12.630 56.590 14.860 58.190 ;
        RECT 9.520 55.220 17.970 56.590 ;
        RECT 6.410 53.850 21.080 55.220 ;
        RECT 3.010 52.710 22.380 53.850 ;
        RECT 12.630 51.110 14.860 52.710 ;
        RECT 9.520 49.740 17.970 51.110 ;
        RECT 6.410 48.370 21.080 49.740 ;
        RECT 3.010 47.230 22.380 48.370 ;
        RECT 12.630 45.630 14.860 47.230 ;
        RECT 9.520 44.260 17.970 45.630 ;
        RECT 6.410 42.890 21.080 44.260 ;
        RECT 3.010 41.750 22.380 42.890 ;
        RECT 12.630 40.150 14.860 41.750 ;
        RECT 9.520 38.780 17.970 40.150 ;
        RECT 6.410 37.410 21.080 38.780 ;
        RECT 3.010 36.270 22.380 37.410 ;
        RECT 12.630 34.670 14.860 36.270 ;
        RECT 9.520 33.300 17.970 34.670 ;
        RECT 6.410 31.930 21.080 33.300 ;
        RECT 3.010 30.790 22.380 31.930 ;
        RECT 12.630 29.190 14.860 30.790 ;
        RECT 9.520 27.820 17.970 29.190 ;
        RECT 6.410 26.450 21.080 27.820 ;
        RECT 3.010 25.310 22.380 26.450 ;
        RECT 12.630 23.710 14.860 25.310 ;
        RECT 9.520 22.340 17.970 23.710 ;
        RECT 6.410 20.970 21.080 22.340 ;
        RECT 3.010 19.830 22.380 20.970 ;
        RECT 12.630 18.230 14.860 19.830 ;
        RECT 9.520 16.860 17.970 18.230 ;
        RECT 6.410 15.490 21.080 16.860 ;
        RECT 3.010 14.350 22.380 15.490 ;
        RECT 12.630 12.750 14.860 14.350 ;
        RECT 9.520 11.380 17.970 12.750 ;
        RECT 6.410 10.010 21.080 11.380 ;
        RECT 3.010 8.870 22.380 10.010 ;
        RECT 12.630 7.270 14.860 8.870 ;
        RECT 9.520 5.900 17.970 7.270 ;
        RECT 6.410 4.530 21.080 5.900 ;
        RECT 3.010 3.460 22.380 4.530 ;
  END
END sram_32x8_9T
END LIBRARY

